VERSION 5.7 ;
BUSBITCHARS "[]" ;
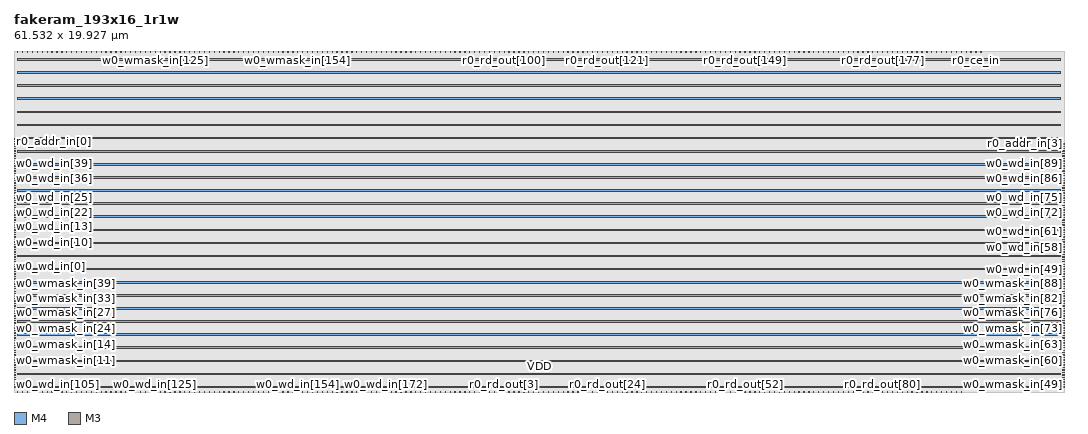
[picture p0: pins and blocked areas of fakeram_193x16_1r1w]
MACRO fakeram_193x16_1r1w
  FOREIGN fakeram_193x16_1r1w 0 0 ;
  SYMMETRY X Y R90 ;
  SIZE 61.532 BY 19.927 ;
  CLASS BLOCK ;
  PIN w0_wmask_in[0]
    DIRECTION INPUT ;
    USE SIGNAL ;
    SHAPE ABUTMENT ;
    PORT
      LAYER M4 ;
      RECT 0.000 0.276 0.072 0.300 ;
    END
  END w0_wmask_in[0]
  PIN w0_wmask_in[1]
    DIRECTION INPUT ;
    USE SIGNAL ;
    SHAPE ABUTMENT ;
    PORT
      LAYER M4 ;
      RECT 0.000 0.420 0.072 0.444 ;
    END
  END w0_wmask_in[1]
  PIN w0_wmask_in[2]
    DIRECTION INPUT ;
    USE SIGNAL ;
    SHAPE ABUTMENT ;
    PORT
      LAYER M4 ;
      RECT 0.000 0.564 0.072 0.588 ;
    END
  END w0_wmask_in[2]
  PIN w0_wmask_in[3]
    DIRECTION INPUT ;
    USE SIGNAL ;
    SHAPE ABUTMENT ;
    PORT
      LAYER M4 ;
      RECT 0.000 0.708 0.072 0.732 ;
    END
  END w0_wmask_in[3]
  PIN w0_wmask_in[4]
    DIRECTION INPUT ;
    USE SIGNAL ;
    SHAPE ABUTMENT ;
    PORT
      LAYER M4 ;
      RECT 0.000 0.852 0.072 0.876 ;
    END
  END w0_wmask_in[4]
  PIN w0_wmask_in[5]
    DIRECTION INPUT ;
    USE SIGNAL ;
    SHAPE ABUTMENT ;
    PORT
      LAYER M4 ;
      RECT 0.000 0.996 0.072 1.020 ;
    END
  END w0_wmask_in[5]
  PIN w0_wmask_in[6]
    DIRECTION INPUT ;
    USE SIGNAL ;
    SHAPE ABUTMENT ;
    PORT
      LAYER M4 ;
      RECT 0.000 1.140 0.072 1.164 ;
    END
  END w0_wmask_in[6]
  PIN w0_wmask_in[7]
    DIRECTION INPUT ;
    USE SIGNAL ;
    SHAPE ABUTMENT ;
    PORT
      LAYER M4 ;
      RECT 0.000 1.284 0.072 1.308 ;
    END
  END w0_wmask_in[7]
  PIN w0_wmask_in[8]
    DIRECTION INPUT ;
    USE SIGNAL ;
    SHAPE ABUTMENT ;
    PORT
      LAYER M4 ;
      RECT 0.000 1.428 0.072 1.452 ;
    END
  END w0_wmask_in[8]
  PIN w0_wmask_in[9]
    DIRECTION INPUT ;
    USE SIGNAL ;
    SHAPE ABUTMENT ;
    PORT
      LAYER M4 ;
      RECT 0.000 1.572 0.072 1.596 ;
    END
  END w0_wmask_in[9]
  PIN w0_wmask_in[10]
    DIRECTION INPUT ;
    USE SIGNAL ;
    SHAPE ABUTMENT ;
    PORT
      LAYER M4 ;
      RECT 0.000 1.716 0.072 1.740 ;
    END
  END w0_wmask_in[10]
  PIN w0_wmask_in[11]
    DIRECTION INPUT ;
    USE SIGNAL ;
    SHAPE ABUTMENT ;
    PORT
      LAYER M4 ;
      RECT 0.000 1.860 0.072 1.884 ;
    END
  END w0_wmask_in[11]
  PIN w0_wmask_in[12]
    DIRECTION INPUT ;
    USE SIGNAL ;
    SHAPE ABUTMENT ;
    PORT
      LAYER M4 ;
      RECT 0.000 2.004 0.072 2.028 ;
    END
  END w0_wmask_in[12]
  PIN w0_wmask_in[13]
    DIRECTION INPUT ;
    USE SIGNAL ;
    SHAPE ABUTMENT ;
    PORT
      LAYER M4 ;
      RECT 0.000 2.148 0.072 2.172 ;
    END
  END w0_wmask_in[13]
  PIN w0_wmask_in[14]
    DIRECTION INPUT ;
    USE SIGNAL ;
    SHAPE ABUTMENT ;
    PORT
      LAYER M4 ;
      RECT 0.000 2.292 0.072 2.316 ;
    END
  END w0_wmask_in[14]
  PIN w0_wmask_in[15]
    DIRECTION INPUT ;
    USE SIGNAL ;
    SHAPE ABUTMENT ;
    PORT
      LAYER M4 ;
      RECT 0.000 2.436 0.072 2.460 ;
    END
  END w0_wmask_in[15]
  PIN w0_wmask_in[16]
    DIRECTION INPUT ;
    USE SIGNAL ;
    SHAPE ABUTMENT ;
    PORT
      LAYER M4 ;
      RECT 0.000 2.580 0.072 2.604 ;
    END
  END w0_wmask_in[16]
  PIN w0_wmask_in[17]
    DIRECTION INPUT ;
    USE SIGNAL ;
    SHAPE ABUTMENT ;
    PORT
      LAYER M4 ;
      RECT 0.000 2.724 0.072 2.748 ;
    END
  END w0_wmask_in[17]
  PIN w0_wmask_in[18]
    DIRECTION INPUT ;
    USE SIGNAL ;
    SHAPE ABUTMENT ;
    PORT
      LAYER M4 ;
      RECT 0.000 2.868 0.072 2.892 ;
    END
  END w0_wmask_in[18]
  PIN w0_wmask_in[19]
    DIRECTION INPUT ;
    USE SIGNAL ;
    SHAPE ABUTMENT ;
    PORT
      LAYER M4 ;
      RECT 0.000 3.012 0.072 3.036 ;
    END
  END w0_wmask_in[19]
  PIN w0_wmask_in[20]
    DIRECTION INPUT ;
    USE SIGNAL ;
    SHAPE ABUTMENT ;
    PORT
      LAYER M4 ;
      RECT 0.000 3.156 0.072 3.180 ;
    END
  END w0_wmask_in[20]
  PIN w0_wmask_in[21]
    DIRECTION INPUT ;
    USE SIGNAL ;
    SHAPE ABUTMENT ;
    PORT
      LAYER M4 ;
      RECT 0.000 3.300 0.072 3.324 ;
    END
  END w0_wmask_in[21]
  PIN w0_wmask_in[22]
    DIRECTION INPUT ;
    USE SIGNAL ;
    SHAPE ABUTMENT ;
    PORT
      LAYER M4 ;
      RECT 0.000 3.444 0.072 3.468 ;
    END
  END w0_wmask_in[22]
  PIN w0_wmask_in[23]
    DIRECTION INPUT ;
    USE SIGNAL ;
    SHAPE ABUTMENT ;
    PORT
      LAYER M4 ;
      RECT 0.000 3.588 0.072 3.612 ;
    END
  END w0_wmask_in[23]
  PIN w0_wmask_in[24]
    DIRECTION INPUT ;
    USE SIGNAL ;
    SHAPE ABUTMENT ;
    PORT
      LAYER M4 ;
      RECT 0.000 3.732 0.072 3.756 ;
    END
  END w0_wmask_in[24]
  PIN w0_wmask_in[25]
    DIRECTION INPUT ;
    USE SIGNAL ;
    SHAPE ABUTMENT ;
    PORT
      LAYER M4 ;
      RECT 0.000 3.876 0.072 3.900 ;
    END
  END w0_wmask_in[25]
  PIN w0_wmask_in[26]
    DIRECTION INPUT ;
    USE SIGNAL ;
    SHAPE ABUTMENT ;
    PORT
      LAYER M4 ;
      RECT 0.000 4.020 0.072 4.044 ;
    END
  END w0_wmask_in[26]
  PIN w0_wmask_in[27]
    DIRECTION INPUT ;
    USE SIGNAL ;
    SHAPE ABUTMENT ;
    PORT
      LAYER M4 ;
      RECT 0.000 4.164 0.072 4.188 ;
    END
  END w0_wmask_in[27]
  PIN w0_wmask_in[28]
    DIRECTION INPUT ;
    USE SIGNAL ;
    SHAPE ABUTMENT ;
    PORT
      LAYER M4 ;
      RECT 0.000 4.308 0.072 4.332 ;
    END
  END w0_wmask_in[28]
  PIN w0_wmask_in[29]
    DIRECTION INPUT ;
    USE SIGNAL ;
    SHAPE ABUTMENT ;
    PORT
      LAYER M4 ;
      RECT 0.000 4.452 0.072 4.476 ;
    END
  END w0_wmask_in[29]
  PIN w0_wmask_in[30]
    DIRECTION INPUT ;
    USE SIGNAL ;
    SHAPE ABUTMENT ;
    PORT
      LAYER M4 ;
      RECT 0.000 4.596 0.072 4.620 ;
    END
  END w0_wmask_in[30]
  PIN w0_wmask_in[31]
    DIRECTION INPUT ;
    USE SIGNAL ;
    SHAPE ABUTMENT ;
    PORT
      LAYER M4 ;
      RECT 0.000 4.740 0.072 4.764 ;
    END
  END w0_wmask_in[31]
  PIN w0_wmask_in[32]
    DIRECTION INPUT ;
    USE SIGNAL ;
    SHAPE ABUTMENT ;
    PORT
      LAYER M4 ;
      RECT 0.000 4.884 0.072 4.908 ;
    END
  END w0_wmask_in[32]
  PIN w0_wmask_in[33]
    DIRECTION INPUT ;
    USE SIGNAL ;
    SHAPE ABUTMENT ;
    PORT
      LAYER M4 ;
      RECT 0.000 5.028 0.072 5.052 ;
    END
  END w0_wmask_in[33]
  PIN w0_wmask_in[34]
    DIRECTION INPUT ;
    USE SIGNAL ;
    SHAPE ABUTMENT ;
    PORT
      LAYER M4 ;
      RECT 0.000 5.172 0.072 5.196 ;
    END
  END w0_wmask_in[34]
  PIN w0_wmask_in[35]
    DIRECTION INPUT ;
    USE SIGNAL ;
    SHAPE ABUTMENT ;
    PORT
      LAYER M4 ;
      RECT 0.000 5.316 0.072 5.340 ;
    END
  END w0_wmask_in[35]
  PIN w0_wmask_in[36]
    DIRECTION INPUT ;
    USE SIGNAL ;
    SHAPE ABUTMENT ;
    PORT
      LAYER M4 ;
      RECT 0.000 5.460 0.072 5.484 ;
    END
  END w0_wmask_in[36]
  PIN w0_wmask_in[37]
    DIRECTION INPUT ;
    USE SIGNAL ;
    SHAPE ABUTMENT ;
    PORT
      LAYER M4 ;
      RECT 0.000 5.604 0.072 5.628 ;
    END
  END w0_wmask_in[37]
  PIN w0_wmask_in[38]
    DIRECTION INPUT ;
    USE SIGNAL ;
    SHAPE ABUTMENT ;
    PORT
      LAYER M4 ;
      RECT 0.000 5.748 0.072 5.772 ;
    END
  END w0_wmask_in[38]
  PIN w0_wmask_in[39]
    DIRECTION INPUT ;
    USE SIGNAL ;
    SHAPE ABUTMENT ;
    PORT
      LAYER M4 ;
      RECT 0.000 5.892 0.072 5.916 ;
    END
  END w0_wmask_in[39]
  PIN w0_wmask_in[40]
    DIRECTION INPUT ;
    USE SIGNAL ;
    SHAPE ABUTMENT ;
    PORT
      LAYER M4 ;
      RECT 0.000 6.036 0.072 6.060 ;
    END
  END w0_wmask_in[40]
  PIN w0_wmask_in[41]
    DIRECTION INPUT ;
    USE SIGNAL ;
    SHAPE ABUTMENT ;
    PORT
      LAYER M4 ;
      RECT 0.000 6.180 0.072 6.204 ;
    END
  END w0_wmask_in[41]
  PIN w0_wmask_in[42]
    DIRECTION INPUT ;
    USE SIGNAL ;
    SHAPE ABUTMENT ;
    PORT
      LAYER M4 ;
      RECT 0.000 6.324 0.072 6.348 ;
    END
  END w0_wmask_in[42]
  PIN w0_wmask_in[43]
    DIRECTION INPUT ;
    USE SIGNAL ;
    SHAPE ABUTMENT ;
    PORT
      LAYER M4 ;
      RECT 0.000 6.468 0.072 6.492 ;
    END
  END w0_wmask_in[43]
  PIN w0_wmask_in[44]
    DIRECTION INPUT ;
    USE SIGNAL ;
    SHAPE ABUTMENT ;
    PORT
      LAYER M4 ;
      RECT 0.000 6.612 0.072 6.636 ;
    END
  END w0_wmask_in[44]
  PIN w0_wmask_in[45]
    DIRECTION INPUT ;
    USE SIGNAL ;
    SHAPE ABUTMENT ;
    PORT
      LAYER M4 ;
      RECT 0.000 6.756 0.072 6.780 ;
    END
  END w0_wmask_in[45]
  PIN w0_wmask_in[46]
    DIRECTION INPUT ;
    USE SIGNAL ;
    SHAPE ABUTMENT ;
    PORT
      LAYER M4 ;
      RECT 0.000 6.900 0.072 6.924 ;
    END
  END w0_wmask_in[46]
  PIN w0_wmask_in[47]
    DIRECTION INPUT ;
    USE SIGNAL ;
    SHAPE ABUTMENT ;
    PORT
      LAYER M4 ;
      RECT 0.000 7.044 0.072 7.068 ;
    END
  END w0_wmask_in[47]
  PIN w0_wmask_in[48]
    DIRECTION INPUT ;
    USE SIGNAL ;
    SHAPE ABUTMENT ;
    PORT
      LAYER M4 ;
      RECT 0.000 7.188 0.072 7.212 ;
    END
  END w0_wmask_in[48]
  PIN w0_wmask_in[49]
    DIRECTION INPUT ;
    USE SIGNAL ;
    SHAPE ABUTMENT ;
    PORT
      LAYER M4 ;
      RECT 61.460 0.276 61.532 0.300 ;
    END
  END w0_wmask_in[49]
  PIN w0_wmask_in[50]
    DIRECTION INPUT ;
    USE SIGNAL ;
    SHAPE ABUTMENT ;
    PORT
      LAYER M4 ;
      RECT 61.460 0.420 61.532 0.444 ;
    END
  END w0_wmask_in[50]
  PIN w0_wmask_in[51]
    DIRECTION INPUT ;
    USE SIGNAL ;
    SHAPE ABUTMENT ;
    PORT
      LAYER M4 ;
      RECT 61.460 0.564 61.532 0.588 ;
    END
  END w0_wmask_in[51]
  PIN w0_wmask_in[52]
    DIRECTION INPUT ;
    USE SIGNAL ;
    SHAPE ABUTMENT ;
    PORT
      LAYER M4 ;
      RECT 61.460 0.708 61.532 0.732 ;
    END
  END w0_wmask_in[52]
  PIN w0_wmask_in[53]
    DIRECTION INPUT ;
    USE SIGNAL ;
    SHAPE ABUTMENT ;
    PORT
      LAYER M4 ;
      RECT 61.460 0.852 61.532 0.876 ;
    END
  END w0_wmask_in[53]
  PIN w0_wmask_in[54]
    DIRECTION INPUT ;
    USE SIGNAL ;
    SHAPE ABUTMENT ;
    PORT
      LAYER M4 ;
      RECT 61.460 0.996 61.532 1.020 ;
    END
  END w0_wmask_in[54]
  PIN w0_wmask_in[55]
    DIRECTION INPUT ;
    USE SIGNAL ;
    SHAPE ABUTMENT ;
    PORT
      LAYER M4 ;
      RECT 61.460 1.140 61.532 1.164 ;
    END
  END w0_wmask_in[55]
  PIN w0_wmask_in[56]
    DIRECTION INPUT ;
    USE SIGNAL ;
    SHAPE ABUTMENT ;
    PORT
      LAYER M4 ;
      RECT 61.460 1.284 61.532 1.308 ;
    END
  END w0_wmask_in[56]
  PIN w0_wmask_in[57]
    DIRECTION INPUT ;
    USE SIGNAL ;
    SHAPE ABUTMENT ;
    PORT
      LAYER M4 ;
      RECT 61.460 1.428 61.532 1.452 ;
    END
  END w0_wmask_in[57]
  PIN w0_wmask_in[58]
    DIRECTION INPUT ;
    USE SIGNAL ;
    SHAPE ABUTMENT ;
    PORT
      LAYER M4 ;
      RECT 61.460 1.572 61.532 1.596 ;
    END
  END w0_wmask_in[58]
  PIN w0_wmask_in[59]
    DIRECTION INPUT ;
    USE SIGNAL ;
    SHAPE ABUTMENT ;
    PORT
      LAYER M4 ;
      RECT 61.460 1.716 61.532 1.740 ;
    END
  END w0_wmask_in[59]
  PIN w0_wmask_in[60]
    DIRECTION INPUT ;
    USE SIGNAL ;
    SHAPE ABUTMENT ;
    PORT
      LAYER M4 ;
      RECT 61.460 1.860 61.532 1.884 ;
    END
  END w0_wmask_in[60]
  PIN w0_wmask_in[61]
    DIRECTION INPUT ;
    USE SIGNAL ;
    SHAPE ABUTMENT ;
    PORT
      LAYER M4 ;
      RECT 61.460 2.004 61.532 2.028 ;
    END
  END w0_wmask_in[61]
  PIN w0_wmask_in[62]
    DIRECTION INPUT ;
    USE SIGNAL ;
    SHAPE ABUTMENT ;
    PORT
      LAYER M4 ;
      RECT 61.460 2.148 61.532 2.172 ;
    END
  END w0_wmask_in[62]
  PIN w0_wmask_in[63]
    DIRECTION INPUT ;
    USE SIGNAL ;
    SHAPE ABUTMENT ;
    PORT
      LAYER M4 ;
      RECT 61.460 2.292 61.532 2.316 ;
    END
  END w0_wmask_in[63]
  PIN w0_wmask_in[64]
    DIRECTION INPUT ;
    USE SIGNAL ;
    SHAPE ABUTMENT ;
    PORT
      LAYER M4 ;
      RECT 61.460 2.436 61.532 2.460 ;
    END
  END w0_wmask_in[64]
  PIN w0_wmask_in[65]
    DIRECTION INPUT ;
    USE SIGNAL ;
    SHAPE ABUTMENT ;
    PORT
      LAYER M4 ;
      RECT 61.460 2.580 61.532 2.604 ;
    END
  END w0_wmask_in[65]
  PIN w0_wmask_in[66]
    DIRECTION INPUT ;
    USE SIGNAL ;
    SHAPE ABUTMENT ;
    PORT
      LAYER M4 ;
      RECT 61.460 2.724 61.532 2.748 ;
    END
  END w0_wmask_in[66]
  PIN w0_wmask_in[67]
    DIRECTION INPUT ;
    USE SIGNAL ;
    SHAPE ABUTMENT ;
    PORT
      LAYER M4 ;
      RECT 61.460 2.868 61.532 2.892 ;
    END
  END w0_wmask_in[67]
  PIN w0_wmask_in[68]
    DIRECTION INPUT ;
    USE SIGNAL ;
    SHAPE ABUTMENT ;
    PORT
      LAYER M4 ;
      RECT 61.460 3.012 61.532 3.036 ;
    END
  END w0_wmask_in[68]
  PIN w0_wmask_in[69]
    DIRECTION INPUT ;
    USE SIGNAL ;
    SHAPE ABUTMENT ;
    PORT
      LAYER M4 ;
      RECT 61.460 3.156 61.532 3.180 ;
    END
  END w0_wmask_in[69]
  PIN w0_wmask_in[70]
    DIRECTION INPUT ;
    USE SIGNAL ;
    SHAPE ABUTMENT ;
    PORT
      LAYER M4 ;
      RECT 61.460 3.300 61.532 3.324 ;
    END
  END w0_wmask_in[70]
  PIN w0_wmask_in[71]
    DIRECTION INPUT ;
    USE SIGNAL ;
    SHAPE ABUTMENT ;
    PORT
      LAYER M4 ;
      RECT 61.460 3.444 61.532 3.468 ;
    END
  END w0_wmask_in[71]
  PIN w0_wmask_in[72]
    DIRECTION INPUT ;
    USE SIGNAL ;
    SHAPE ABUTMENT ;
    PORT
      LAYER M4 ;
      RECT 61.460 3.588 61.532 3.612 ;
    END
  END w0_wmask_in[72]
  PIN w0_wmask_in[73]
    DIRECTION INPUT ;
    USE SIGNAL ;
    SHAPE ABUTMENT ;
    PORT
      LAYER M4 ;
      RECT 61.460 3.732 61.532 3.756 ;
    END
  END w0_wmask_in[73]
  PIN w0_wmask_in[74]
    DIRECTION INPUT ;
    USE SIGNAL ;
    SHAPE ABUTMENT ;
    PORT
      LAYER M4 ;
      RECT 61.460 3.876 61.532 3.900 ;
    END
  END w0_wmask_in[74]
  PIN w0_wmask_in[75]
    DIRECTION INPUT ;
    USE SIGNAL ;
    SHAPE ABUTMENT ;
    PORT
      LAYER M4 ;
      RECT 61.460 4.020 61.532 4.044 ;
    END
  END w0_wmask_in[75]
  PIN w0_wmask_in[76]
    DIRECTION INPUT ;
    USE SIGNAL ;
    SHAPE ABUTMENT ;
    PORT
      LAYER M4 ;
      RECT 61.460 4.164 61.532 4.188 ;
    END
  END w0_wmask_in[76]
  PIN w0_wmask_in[77]
    DIRECTION INPUT ;
    USE SIGNAL ;
    SHAPE ABUTMENT ;
    PORT
      LAYER M4 ;
      RECT 61.460 4.308 61.532 4.332 ;
    END
  END w0_wmask_in[77]
  PIN w0_wmask_in[78]
    DIRECTION INPUT ;
    USE SIGNAL ;
    SHAPE ABUTMENT ;
    PORT
      LAYER M4 ;
      RECT 61.460 4.452 61.532 4.476 ;
    END
  END w0_wmask_in[78]
  PIN w0_wmask_in[79]
    DIRECTION INPUT ;
    USE SIGNAL ;
    SHAPE ABUTMENT ;
    PORT
      LAYER M4 ;
      RECT 61.460 4.596 61.532 4.620 ;
    END
  END w0_wmask_in[79]
  PIN w0_wmask_in[80]
    DIRECTION INPUT ;
    USE SIGNAL ;
    SHAPE ABUTMENT ;
    PORT
      LAYER M4 ;
      RECT 61.460 4.740 61.532 4.764 ;
    END
  END w0_wmask_in[80]
  PIN w0_wmask_in[81]
    DIRECTION INPUT ;
    USE SIGNAL ;
    SHAPE ABUTMENT ;
    PORT
      LAYER M4 ;
      RECT 61.460 4.884 61.532 4.908 ;
    END
  END w0_wmask_in[81]
  PIN w0_wmask_in[82]
    DIRECTION INPUT ;
    USE SIGNAL ;
    SHAPE ABUTMENT ;
    PORT
      LAYER M4 ;
      RECT 61.460 5.028 61.532 5.052 ;
    END
  END w0_wmask_in[82]
  PIN w0_wmask_in[83]
    DIRECTION INPUT ;
    USE SIGNAL ;
    SHAPE ABUTMENT ;
    PORT
      LAYER M4 ;
      RECT 61.460 5.172 61.532 5.196 ;
    END
  END w0_wmask_in[83]
  PIN w0_wmask_in[84]
    DIRECTION INPUT ;
    USE SIGNAL ;
    SHAPE ABUTMENT ;
    PORT
      LAYER M4 ;
      RECT 61.460 5.316 61.532 5.340 ;
    END
  END w0_wmask_in[84]
  PIN w0_wmask_in[85]
    DIRECTION INPUT ;
    USE SIGNAL ;
    SHAPE ABUTMENT ;
    PORT
      LAYER M4 ;
      RECT 61.460 5.460 61.532 5.484 ;
    END
  END w0_wmask_in[85]
  PIN w0_wmask_in[86]
    DIRECTION INPUT ;
    USE SIGNAL ;
    SHAPE ABUTMENT ;
    PORT
      LAYER M4 ;
      RECT 61.460 5.604 61.532 5.628 ;
    END
  END w0_wmask_in[86]
  PIN w0_wmask_in[87]
    DIRECTION INPUT ;
    USE SIGNAL ;
    SHAPE ABUTMENT ;
    PORT
      LAYER M4 ;
      RECT 61.460 5.748 61.532 5.772 ;
    END
  END w0_wmask_in[87]
  PIN w0_wmask_in[88]
    DIRECTION INPUT ;
    USE SIGNAL ;
    SHAPE ABUTMENT ;
    PORT
      LAYER M4 ;
      RECT 61.460 5.892 61.532 5.916 ;
    END
  END w0_wmask_in[88]
  PIN w0_wmask_in[89]
    DIRECTION INPUT ;
    USE SIGNAL ;
    SHAPE ABUTMENT ;
    PORT
      LAYER M4 ;
      RECT 61.460 6.036 61.532 6.060 ;
    END
  END w0_wmask_in[89]
  PIN w0_wmask_in[90]
    DIRECTION INPUT ;
    USE SIGNAL ;
    SHAPE ABUTMENT ;
    PORT
      LAYER M4 ;
      RECT 61.460 6.180 61.532 6.204 ;
    END
  END w0_wmask_in[90]
  PIN w0_wmask_in[91]
    DIRECTION INPUT ;
    USE SIGNAL ;
    SHAPE ABUTMENT ;
    PORT
      LAYER M4 ;
      RECT 61.460 6.324 61.532 6.348 ;
    END
  END w0_wmask_in[91]
  PIN w0_wmask_in[92]
    DIRECTION INPUT ;
    USE SIGNAL ;
    SHAPE ABUTMENT ;
    PORT
      LAYER M4 ;
      RECT 61.460 6.468 61.532 6.492 ;
    END
  END w0_wmask_in[92]
  PIN w0_wmask_in[93]
    DIRECTION INPUT ;
    USE SIGNAL ;
    SHAPE ABUTMENT ;
    PORT
      LAYER M4 ;
      RECT 61.460 6.612 61.532 6.636 ;
    END
  END w0_wmask_in[93]
  PIN w0_wmask_in[94]
    DIRECTION INPUT ;
    USE SIGNAL ;
    SHAPE ABUTMENT ;
    PORT
      LAYER M4 ;
      RECT 61.460 6.756 61.532 6.780 ;
    END
  END w0_wmask_in[94]
  PIN w0_wmask_in[95]
    DIRECTION INPUT ;
    USE SIGNAL ;
    SHAPE ABUTMENT ;
    PORT
      LAYER M4 ;
      RECT 61.460 6.900 61.532 6.924 ;
    END
  END w0_wmask_in[95]
  PIN w0_wmask_in[96]
    DIRECTION INPUT ;
    USE SIGNAL ;
    SHAPE ABUTMENT ;
    PORT
      LAYER M4 ;
      RECT 61.460 7.044 61.532 7.068 ;
    END
  END w0_wmask_in[96]
  PIN w0_wmask_in[97]
    DIRECTION INPUT ;
    USE SIGNAL ;
    SHAPE ABUTMENT ;
    PORT
      LAYER M3 ;
      RECT 0.207 19.873 0.225 19.927 ;
    END
  END w0_wmask_in[97]
  PIN w0_wmask_in[98]
    DIRECTION INPUT ;
    USE SIGNAL ;
    SHAPE ABUTMENT ;
    PORT
      LAYER M3 ;
      RECT 0.495 19.873 0.513 19.927 ;
    END
  END w0_wmask_in[98]
  PIN w0_wmask_in[99]
    DIRECTION INPUT ;
    USE SIGNAL ;
    SHAPE ABUTMENT ;
    PORT
      LAYER M3 ;
      RECT 0.783 19.873 0.801 19.927 ;
    END
  END w0_wmask_in[99]
  PIN w0_wmask_in[100]
    DIRECTION INPUT ;
    USE SIGNAL ;
    SHAPE ABUTMENT ;
    PORT
      LAYER M3 ;
      RECT 1.071 19.873 1.089 19.927 ;
    END
  END w0_wmask_in[100]
  PIN w0_wmask_in[101]
    DIRECTION INPUT ;
    USE SIGNAL ;
    SHAPE ABUTMENT ;
    PORT
      LAYER M3 ;
      RECT 1.359 19.873 1.377 19.927 ;
    END
  END w0_wmask_in[101]
  PIN w0_wmask_in[102]
    DIRECTION INPUT ;
    USE SIGNAL ;
    SHAPE ABUTMENT ;
    PORT
      LAYER M3 ;
      RECT 1.647 19.873 1.665 19.927 ;
    END
  END w0_wmask_in[102]
  PIN w0_wmask_in[103]
    DIRECTION INPUT ;
    USE SIGNAL ;
    SHAPE ABUTMENT ;
    PORT
      LAYER M3 ;
      RECT 1.935 19.873 1.953 19.927 ;
    END
  END w0_wmask_in[103]
  PIN w0_wmask_in[104]
    DIRECTION INPUT ;
    USE SIGNAL ;
    SHAPE ABUTMENT ;
    PORT
      LAYER M3 ;
      RECT 2.223 19.873 2.241 19.927 ;
    END
  END w0_wmask_in[104]
  PIN w0_wmask_in[105]
    DIRECTION INPUT ;
    USE SIGNAL ;
    SHAPE ABUTMENT ;
    PORT
      LAYER M3 ;
      RECT 2.511 19.873 2.529 19.927 ;
    END
  END w0_wmask_in[105]
  PIN w0_wmask_in[106]
    DIRECTION INPUT ;
    USE SIGNAL ;
    SHAPE ABUTMENT ;
    PORT
      LAYER M3 ;
      RECT 2.799 19.873 2.817 19.927 ;
    END
  END w0_wmask_in[106]
  PIN w0_wmask_in[107]
    DIRECTION INPUT ;
    USE SIGNAL ;
    SHAPE ABUTMENT ;
    PORT
      LAYER M3 ;
      RECT 3.087 19.873 3.105 19.927 ;
    END
  END w0_wmask_in[107]
  PIN w0_wmask_in[108]
    DIRECTION INPUT ;
    USE SIGNAL ;
    SHAPE ABUTMENT ;
    PORT
      LAYER M3 ;
      RECT 3.375 19.873 3.393 19.927 ;
    END
  END w0_wmask_in[108]
  PIN w0_wmask_in[109]
    DIRECTION INPUT ;
    USE SIGNAL ;
    SHAPE ABUTMENT ;
    PORT
      LAYER M3 ;
      RECT 3.663 19.873 3.681 19.927 ;
    END
  END w0_wmask_in[109]
  PIN w0_wmask_in[110]
    DIRECTION INPUT ;
    USE SIGNAL ;
    SHAPE ABUTMENT ;
    PORT
      LAYER M3 ;
      RECT 3.951 19.873 3.969 19.927 ;
    END
  END w0_wmask_in[110]
  PIN w0_wmask_in[111]
    DIRECTION INPUT ;
    USE SIGNAL ;
    SHAPE ABUTMENT ;
    PORT
      LAYER M3 ;
      RECT 4.239 19.873 4.257 19.927 ;
    END
  END w0_wmask_in[111]
  PIN w0_wmask_in[112]
    DIRECTION INPUT ;
    USE SIGNAL ;
    SHAPE ABUTMENT ;
    PORT
      LAYER M3 ;
      RECT 4.527 19.873 4.545 19.927 ;
    END
  END w0_wmask_in[112]
  PIN w0_wmask_in[113]
    DIRECTION INPUT ;
    USE SIGNAL ;
    SHAPE ABUTMENT ;
    PORT
      LAYER M3 ;
      RECT 4.815 19.873 4.833 19.927 ;
    END
  END w0_wmask_in[113]
  PIN w0_wmask_in[114]
    DIRECTION INPUT ;
    USE SIGNAL ;
    SHAPE ABUTMENT ;
    PORT
      LAYER M3 ;
      RECT 5.103 19.873 5.121 19.927 ;
    END
  END w0_wmask_in[114]
  PIN w0_wmask_in[115]
    DIRECTION INPUT ;
    USE SIGNAL ;
    SHAPE ABUTMENT ;
    PORT
      LAYER M3 ;
      RECT 5.391 19.873 5.409 19.927 ;
    END
  END w0_wmask_in[115]
  PIN w0_wmask_in[116]
    DIRECTION INPUT ;
    USE SIGNAL ;
    SHAPE ABUTMENT ;
    PORT
      LAYER M3 ;
      RECT 5.679 19.873 5.697 19.927 ;
    END
  END w0_wmask_in[116]
  PIN w0_wmask_in[117]
    DIRECTION INPUT ;
    USE SIGNAL ;
    SHAPE ABUTMENT ;
    PORT
      LAYER M3 ;
      RECT 5.967 19.873 5.985 19.927 ;
    END
  END w0_wmask_in[117]
  PIN w0_wmask_in[118]
    DIRECTION INPUT ;
    USE SIGNAL ;
    SHAPE ABUTMENT ;
    PORT
      LAYER M3 ;
      RECT 6.255 19.873 6.273 19.927 ;
    END
  END w0_wmask_in[118]
  PIN w0_wmask_in[119]
    DIRECTION INPUT ;
    USE SIGNAL ;
    SHAPE ABUTMENT ;
    PORT
      LAYER M3 ;
      RECT 6.543 19.873 6.561 19.927 ;
    END
  END w0_wmask_in[119]
  PIN w0_wmask_in[120]
    DIRECTION INPUT ;
    USE SIGNAL ;
    SHAPE ABUTMENT ;
    PORT
      LAYER M3 ;
      RECT 6.831 19.873 6.849 19.927 ;
    END
  END w0_wmask_in[120]
  PIN w0_wmask_in[121]
    DIRECTION INPUT ;
    USE SIGNAL ;
    SHAPE ABUTMENT ;
    PORT
      LAYER M3 ;
      RECT 7.119 19.873 7.137 19.927 ;
    END
  END w0_wmask_in[121]
  PIN w0_wmask_in[122]
    DIRECTION INPUT ;
    USE SIGNAL ;
    SHAPE ABUTMENT ;
    PORT
      LAYER M3 ;
      RECT 7.407 19.873 7.425 19.927 ;
    END
  END w0_wmask_in[122]
  PIN w0_wmask_in[123]
    DIRECTION INPUT ;
    USE SIGNAL ;
    SHAPE ABUTMENT ;
    PORT
      LAYER M3 ;
      RECT 7.695 19.873 7.713 19.927 ;
    END
  END w0_wmask_in[123]
  PIN w0_wmask_in[124]
    DIRECTION INPUT ;
    USE SIGNAL ;
    SHAPE ABUTMENT ;
    PORT
      LAYER M3 ;
      RECT 7.983 19.873 8.001 19.927 ;
    END
  END w0_wmask_in[124]
  PIN w0_wmask_in[125]
    DIRECTION INPUT ;
    USE SIGNAL ;
    SHAPE ABUTMENT ;
    PORT
      LAYER M3 ;
      RECT 8.271 19.873 8.289 19.927 ;
    END
  END w0_wmask_in[125]
  PIN w0_wmask_in[126]
    DIRECTION INPUT ;
    USE SIGNAL ;
    SHAPE ABUTMENT ;
    PORT
      LAYER M3 ;
      RECT 8.559 19.873 8.577 19.927 ;
    END
  END w0_wmask_in[126]
  PIN w0_wmask_in[127]
    DIRECTION INPUT ;
    USE SIGNAL ;
    SHAPE ABUTMENT ;
    PORT
      LAYER M3 ;
      RECT 8.847 19.873 8.865 19.927 ;
    END
  END w0_wmask_in[127]
  PIN w0_wmask_in[128]
    DIRECTION INPUT ;
    USE SIGNAL ;
    SHAPE ABUTMENT ;
    PORT
      LAYER M3 ;
      RECT 9.135 19.873 9.153 19.927 ;
    END
  END w0_wmask_in[128]
  PIN w0_wmask_in[129]
    DIRECTION INPUT ;
    USE SIGNAL ;
    SHAPE ABUTMENT ;
    PORT
      LAYER M3 ;
      RECT 9.423 19.873 9.441 19.927 ;
    END
  END w0_wmask_in[129]
  PIN w0_wmask_in[130]
    DIRECTION INPUT ;
    USE SIGNAL ;
    SHAPE ABUTMENT ;
    PORT
      LAYER M3 ;
      RECT 9.711 19.873 9.729 19.927 ;
    END
  END w0_wmask_in[130]
  PIN w0_wmask_in[131]
    DIRECTION INPUT ;
    USE SIGNAL ;
    SHAPE ABUTMENT ;
    PORT
      LAYER M3 ;
      RECT 9.999 19.873 10.017 19.927 ;
    END
  END w0_wmask_in[131]
  PIN w0_wmask_in[132]
    DIRECTION INPUT ;
    USE SIGNAL ;
    SHAPE ABUTMENT ;
    PORT
      LAYER M3 ;
      RECT 10.287 19.873 10.305 19.927 ;
    END
  END w0_wmask_in[132]
  PIN w0_wmask_in[133]
    DIRECTION INPUT ;
    USE SIGNAL ;
    SHAPE ABUTMENT ;
    PORT
      LAYER M3 ;
      RECT 10.575 19.873 10.593 19.927 ;
    END
  END w0_wmask_in[133]
  PIN w0_wmask_in[134]
    DIRECTION INPUT ;
    USE SIGNAL ;
    SHAPE ABUTMENT ;
    PORT
      LAYER M3 ;
      RECT 10.863 19.873 10.881 19.927 ;
    END
  END w0_wmask_in[134]
  PIN w0_wmask_in[135]
    DIRECTION INPUT ;
    USE SIGNAL ;
    SHAPE ABUTMENT ;
    PORT
      LAYER M3 ;
      RECT 11.151 19.873 11.169 19.927 ;
    END
  END w0_wmask_in[135]
  PIN w0_wmask_in[136]
    DIRECTION INPUT ;
    USE SIGNAL ;
    SHAPE ABUTMENT ;
    PORT
      LAYER M3 ;
      RECT 11.439 19.873 11.457 19.927 ;
    END
  END w0_wmask_in[136]
  PIN w0_wmask_in[137]
    DIRECTION INPUT ;
    USE SIGNAL ;
    SHAPE ABUTMENT ;
    PORT
      LAYER M3 ;
      RECT 11.727 19.873 11.745 19.927 ;
    END
  END w0_wmask_in[137]
  PIN w0_wmask_in[138]
    DIRECTION INPUT ;
    USE SIGNAL ;
    SHAPE ABUTMENT ;
    PORT
      LAYER M3 ;
      RECT 12.015 19.873 12.033 19.927 ;
    END
  END w0_wmask_in[138]
  PIN w0_wmask_in[139]
    DIRECTION INPUT ;
    USE SIGNAL ;
    SHAPE ABUTMENT ;
    PORT
      LAYER M3 ;
      RECT 12.303 19.873 12.321 19.927 ;
    END
  END w0_wmask_in[139]
  PIN w0_wmask_in[140]
    DIRECTION INPUT ;
    USE SIGNAL ;
    SHAPE ABUTMENT ;
    PORT
      LAYER M3 ;
      RECT 12.591 19.873 12.609 19.927 ;
    END
  END w0_wmask_in[140]
  PIN w0_wmask_in[141]
    DIRECTION INPUT ;
    USE SIGNAL ;
    SHAPE ABUTMENT ;
    PORT
      LAYER M3 ;
      RECT 12.879 19.873 12.897 19.927 ;
    END
  END w0_wmask_in[141]
  PIN w0_wmask_in[142]
    DIRECTION INPUT ;
    USE SIGNAL ;
    SHAPE ABUTMENT ;
    PORT
      LAYER M3 ;
      RECT 13.167 19.873 13.185 19.927 ;
    END
  END w0_wmask_in[142]
  PIN w0_wmask_in[143]
    DIRECTION INPUT ;
    USE SIGNAL ;
    SHAPE ABUTMENT ;
    PORT
      LAYER M3 ;
      RECT 13.455 19.873 13.473 19.927 ;
    END
  END w0_wmask_in[143]
  PIN w0_wmask_in[144]
    DIRECTION INPUT ;
    USE SIGNAL ;
    SHAPE ABUTMENT ;
    PORT
      LAYER M3 ;
      RECT 13.743 19.873 13.761 19.927 ;
    END
  END w0_wmask_in[144]
  PIN w0_wmask_in[145]
    DIRECTION INPUT ;
    USE SIGNAL ;
    SHAPE ABUTMENT ;
    PORT
      LAYER M3 ;
      RECT 14.031 19.873 14.049 19.927 ;
    END
  END w0_wmask_in[145]
  PIN w0_wmask_in[146]
    DIRECTION INPUT ;
    USE SIGNAL ;
    SHAPE ABUTMENT ;
    PORT
      LAYER M3 ;
      RECT 14.319 19.873 14.337 19.927 ;
    END
  END w0_wmask_in[146]
  PIN w0_wmask_in[147]
    DIRECTION INPUT ;
    USE SIGNAL ;
    SHAPE ABUTMENT ;
    PORT
      LAYER M3 ;
      RECT 14.607 19.873 14.625 19.927 ;
    END
  END w0_wmask_in[147]
  PIN w0_wmask_in[148]
    DIRECTION INPUT ;
    USE SIGNAL ;
    SHAPE ABUTMENT ;
    PORT
      LAYER M3 ;
      RECT 14.895 19.873 14.913 19.927 ;
    END
  END w0_wmask_in[148]
  PIN w0_wmask_in[149]
    DIRECTION INPUT ;
    USE SIGNAL ;
    SHAPE ABUTMENT ;
    PORT
      LAYER M3 ;
      RECT 15.183 19.873 15.201 19.927 ;
    END
  END w0_wmask_in[149]
  PIN w0_wmask_in[150]
    DIRECTION INPUT ;
    USE SIGNAL ;
    SHAPE ABUTMENT ;
    PORT
      LAYER M3 ;
      RECT 15.471 19.873 15.489 19.927 ;
    END
  END w0_wmask_in[150]
  PIN w0_wmask_in[151]
    DIRECTION INPUT ;
    USE SIGNAL ;
    SHAPE ABUTMENT ;
    PORT
      LAYER M3 ;
      RECT 15.759 19.873 15.777 19.927 ;
    END
  END w0_wmask_in[151]
  PIN w0_wmask_in[152]
    DIRECTION INPUT ;
    USE SIGNAL ;
    SHAPE ABUTMENT ;
    PORT
      LAYER M3 ;
      RECT 16.047 19.873 16.065 19.927 ;
    END
  END w0_wmask_in[152]
  PIN w0_wmask_in[153]
    DIRECTION INPUT ;
    USE SIGNAL ;
    SHAPE ABUTMENT ;
    PORT
      LAYER M3 ;
      RECT 16.335 19.873 16.353 19.927 ;
    END
  END w0_wmask_in[153]
  PIN w0_wmask_in[154]
    DIRECTION INPUT ;
    USE SIGNAL ;
    SHAPE ABUTMENT ;
    PORT
      LAYER M3 ;
      RECT 16.623 19.873 16.641 19.927 ;
    END
  END w0_wmask_in[154]
  PIN w0_wmask_in[155]
    DIRECTION INPUT ;
    USE SIGNAL ;
    SHAPE ABUTMENT ;
    PORT
      LAYER M3 ;
      RECT 16.911 19.873 16.929 19.927 ;
    END
  END w0_wmask_in[155]
  PIN w0_wmask_in[156]
    DIRECTION INPUT ;
    USE SIGNAL ;
    SHAPE ABUTMENT ;
    PORT
      LAYER M3 ;
      RECT 17.199 19.873 17.217 19.927 ;
    END
  END w0_wmask_in[156]
  PIN w0_wmask_in[157]
    DIRECTION INPUT ;
    USE SIGNAL ;
    SHAPE ABUTMENT ;
    PORT
      LAYER M3 ;
      RECT 17.487 19.873 17.505 19.927 ;
    END
  END w0_wmask_in[157]
  PIN w0_wmask_in[158]
    DIRECTION INPUT ;
    USE SIGNAL ;
    SHAPE ABUTMENT ;
    PORT
      LAYER M3 ;
      RECT 17.775 19.873 17.793 19.927 ;
    END
  END w0_wmask_in[158]
  PIN w0_wmask_in[159]
    DIRECTION INPUT ;
    USE SIGNAL ;
    SHAPE ABUTMENT ;
    PORT
      LAYER M3 ;
      RECT 18.063 19.873 18.081 19.927 ;
    END
  END w0_wmask_in[159]
  PIN w0_wmask_in[160]
    DIRECTION INPUT ;
    USE SIGNAL ;
    SHAPE ABUTMENT ;
    PORT
      LAYER M3 ;
      RECT 18.351 19.873 18.369 19.927 ;
    END
  END w0_wmask_in[160]
  PIN w0_wmask_in[161]
    DIRECTION INPUT ;
    USE SIGNAL ;
    SHAPE ABUTMENT ;
    PORT
      LAYER M3 ;
      RECT 18.639 19.873 18.657 19.927 ;
    END
  END w0_wmask_in[161]
  PIN w0_wmask_in[162]
    DIRECTION INPUT ;
    USE SIGNAL ;
    SHAPE ABUTMENT ;
    PORT
      LAYER M3 ;
      RECT 18.927 19.873 18.945 19.927 ;
    END
  END w0_wmask_in[162]
  PIN w0_wmask_in[163]
    DIRECTION INPUT ;
    USE SIGNAL ;
    SHAPE ABUTMENT ;
    PORT
      LAYER M3 ;
      RECT 19.215 19.873 19.233 19.927 ;
    END
  END w0_wmask_in[163]
  PIN w0_wmask_in[164]
    DIRECTION INPUT ;
    USE SIGNAL ;
    SHAPE ABUTMENT ;
    PORT
      LAYER M3 ;
      RECT 19.503 19.873 19.521 19.927 ;
    END
  END w0_wmask_in[164]
  PIN w0_wmask_in[165]
    DIRECTION INPUT ;
    USE SIGNAL ;
    SHAPE ABUTMENT ;
    PORT
      LAYER M3 ;
      RECT 19.791 19.873 19.809 19.927 ;
    END
  END w0_wmask_in[165]
  PIN w0_wmask_in[166]
    DIRECTION INPUT ;
    USE SIGNAL ;
    SHAPE ABUTMENT ;
    PORT
      LAYER M3 ;
      RECT 20.079 19.873 20.097 19.927 ;
    END
  END w0_wmask_in[166]
  PIN w0_wmask_in[167]
    DIRECTION INPUT ;
    USE SIGNAL ;
    SHAPE ABUTMENT ;
    PORT
      LAYER M3 ;
      RECT 20.367 19.873 20.385 19.927 ;
    END
  END w0_wmask_in[167]
  PIN w0_wmask_in[168]
    DIRECTION INPUT ;
    USE SIGNAL ;
    SHAPE ABUTMENT ;
    PORT
      LAYER M3 ;
      RECT 20.655 19.873 20.673 19.927 ;
    END
  END w0_wmask_in[168]
  PIN w0_wmask_in[169]
    DIRECTION INPUT ;
    USE SIGNAL ;
    SHAPE ABUTMENT ;
    PORT
      LAYER M3 ;
      RECT 20.943 19.873 20.961 19.927 ;
    END
  END w0_wmask_in[169]
  PIN w0_wmask_in[170]
    DIRECTION INPUT ;
    USE SIGNAL ;
    SHAPE ABUTMENT ;
    PORT
      LAYER M3 ;
      RECT 21.231 19.873 21.249 19.927 ;
    END
  END w0_wmask_in[170]
  PIN w0_wmask_in[171]
    DIRECTION INPUT ;
    USE SIGNAL ;
    SHAPE ABUTMENT ;
    PORT
      LAYER M3 ;
      RECT 21.519 19.873 21.537 19.927 ;
    END
  END w0_wmask_in[171]
  PIN w0_wmask_in[172]
    DIRECTION INPUT ;
    USE SIGNAL ;
    SHAPE ABUTMENT ;
    PORT
      LAYER M3 ;
      RECT 21.807 19.873 21.825 19.927 ;
    END
  END w0_wmask_in[172]
  PIN w0_wmask_in[173]
    DIRECTION INPUT ;
    USE SIGNAL ;
    SHAPE ABUTMENT ;
    PORT
      LAYER M3 ;
      RECT 22.095 19.873 22.113 19.927 ;
    END
  END w0_wmask_in[173]
  PIN w0_wmask_in[174]
    DIRECTION INPUT ;
    USE SIGNAL ;
    SHAPE ABUTMENT ;
    PORT
      LAYER M3 ;
      RECT 22.383 19.873 22.401 19.927 ;
    END
  END w0_wmask_in[174]
  PIN w0_wmask_in[175]
    DIRECTION INPUT ;
    USE SIGNAL ;
    SHAPE ABUTMENT ;
    PORT
      LAYER M3 ;
      RECT 22.671 19.873 22.689 19.927 ;
    END
  END w0_wmask_in[175]
  PIN w0_wmask_in[176]
    DIRECTION INPUT ;
    USE SIGNAL ;
    SHAPE ABUTMENT ;
    PORT
      LAYER M3 ;
      RECT 22.959 19.873 22.977 19.927 ;
    END
  END w0_wmask_in[176]
  PIN w0_wmask_in[177]
    DIRECTION INPUT ;
    USE SIGNAL ;
    SHAPE ABUTMENT ;
    PORT
      LAYER M3 ;
      RECT 23.247 19.873 23.265 19.927 ;
    END
  END w0_wmask_in[177]
  PIN w0_wmask_in[178]
    DIRECTION INPUT ;
    USE SIGNAL ;
    SHAPE ABUTMENT ;
    PORT
      LAYER M3 ;
      RECT 23.535 19.873 23.553 19.927 ;
    END
  END w0_wmask_in[178]
  PIN w0_wmask_in[179]
    DIRECTION INPUT ;
    USE SIGNAL ;
    SHAPE ABUTMENT ;
    PORT
      LAYER M3 ;
      RECT 23.823 19.873 23.841 19.927 ;
    END
  END w0_wmask_in[179]
  PIN w0_wmask_in[180]
    DIRECTION INPUT ;
    USE SIGNAL ;
    SHAPE ABUTMENT ;
    PORT
      LAYER M3 ;
      RECT 24.111 19.873 24.129 19.927 ;
    END
  END w0_wmask_in[180]
  PIN w0_wmask_in[181]
    DIRECTION INPUT ;
    USE SIGNAL ;
    SHAPE ABUTMENT ;
    PORT
      LAYER M3 ;
      RECT 24.399 19.873 24.417 19.927 ;
    END
  END w0_wmask_in[181]
  PIN w0_wmask_in[182]
    DIRECTION INPUT ;
    USE SIGNAL ;
    SHAPE ABUTMENT ;
    PORT
      LAYER M3 ;
      RECT 24.687 19.873 24.705 19.927 ;
    END
  END w0_wmask_in[182]
  PIN w0_wmask_in[183]
    DIRECTION INPUT ;
    USE SIGNAL ;
    SHAPE ABUTMENT ;
    PORT
      LAYER M3 ;
      RECT 24.975 19.873 24.993 19.927 ;
    END
  END w0_wmask_in[183]
  PIN w0_wmask_in[184]
    DIRECTION INPUT ;
    USE SIGNAL ;
    SHAPE ABUTMENT ;
    PORT
      LAYER M3 ;
      RECT 25.263 19.873 25.281 19.927 ;
    END
  END w0_wmask_in[184]
  PIN w0_wmask_in[185]
    DIRECTION INPUT ;
    USE SIGNAL ;
    SHAPE ABUTMENT ;
    PORT
      LAYER M3 ;
      RECT 25.551 19.873 25.569 19.927 ;
    END
  END w0_wmask_in[185]
  PIN w0_wmask_in[186]
    DIRECTION INPUT ;
    USE SIGNAL ;
    SHAPE ABUTMENT ;
    PORT
      LAYER M3 ;
      RECT 25.839 19.873 25.857 19.927 ;
    END
  END w0_wmask_in[186]
  PIN w0_wmask_in[187]
    DIRECTION INPUT ;
    USE SIGNAL ;
    SHAPE ABUTMENT ;
    PORT
      LAYER M3 ;
      RECT 26.127 19.873 26.145 19.927 ;
    END
  END w0_wmask_in[187]
  PIN w0_wmask_in[188]
    DIRECTION INPUT ;
    USE SIGNAL ;
    SHAPE ABUTMENT ;
    PORT
      LAYER M3 ;
      RECT 26.415 19.873 26.433 19.927 ;
    END
  END w0_wmask_in[188]
  PIN w0_wmask_in[189]
    DIRECTION INPUT ;
    USE SIGNAL ;
    SHAPE ABUTMENT ;
    PORT
      LAYER M3 ;
      RECT 26.703 19.873 26.721 19.927 ;
    END
  END w0_wmask_in[189]
  PIN w0_wmask_in[190]
    DIRECTION INPUT ;
    USE SIGNAL ;
    SHAPE ABUTMENT ;
    PORT
      LAYER M3 ;
      RECT 26.991 19.873 27.009 19.927 ;
    END
  END w0_wmask_in[190]
  PIN w0_wmask_in[191]
    DIRECTION INPUT ;
    USE SIGNAL ;
    SHAPE ABUTMENT ;
    PORT
      LAYER M3 ;
      RECT 27.279 19.873 27.297 19.927 ;
    END
  END w0_wmask_in[191]
  PIN w0_wmask_in[192]
    DIRECTION INPUT ;
    USE SIGNAL ;
    SHAPE ABUTMENT ;
    PORT
      LAYER M3 ;
      RECT 27.567 19.873 27.585 19.927 ;
    END
  END w0_wmask_in[192]
  PIN w0_wd_in[0]
    DIRECTION INPUT ;
    USE SIGNAL ;
    SHAPE ABUTMENT ;
    PORT
      LAYER M4 ;
      RECT 0.000 7.332 0.072 7.356 ;
    END
  END w0_wd_in[0]
  PIN w0_wd_in[1]
    DIRECTION INPUT ;
    USE SIGNAL ;
    SHAPE ABUTMENT ;
    PORT
      LAYER M4 ;
      RECT 0.000 7.476 0.072 7.500 ;
    END
  END w0_wd_in[1]
  PIN w0_wd_in[2]
    DIRECTION INPUT ;
    USE SIGNAL ;
    SHAPE ABUTMENT ;
    PORT
      LAYER M4 ;
      RECT 0.000 7.620 0.072 7.644 ;
    END
  END w0_wd_in[2]
  PIN w0_wd_in[3]
    DIRECTION INPUT ;
    USE SIGNAL ;
    SHAPE ABUTMENT ;
    PORT
      LAYER M4 ;
      RECT 0.000 7.764 0.072 7.788 ;
    END
  END w0_wd_in[3]
  PIN w0_wd_in[4]
    DIRECTION INPUT ;
    USE SIGNAL ;
    SHAPE ABUTMENT ;
    PORT
      LAYER M4 ;
      RECT 0.000 7.908 0.072 7.932 ;
    END
  END w0_wd_in[4]
  PIN w0_wd_in[5]
    DIRECTION INPUT ;
    USE SIGNAL ;
    SHAPE ABUTMENT ;
    PORT
      LAYER M4 ;
      RECT 0.000 8.052 0.072 8.076 ;
    END
  END w0_wd_in[5]
  PIN w0_wd_in[6]
    DIRECTION INPUT ;
    USE SIGNAL ;
    SHAPE ABUTMENT ;
    PORT
      LAYER M4 ;
      RECT 0.000 8.196 0.072 8.220 ;
    END
  END w0_wd_in[6]
  PIN w0_wd_in[7]
    DIRECTION INPUT ;
    USE SIGNAL ;
    SHAPE ABUTMENT ;
    PORT
      LAYER M4 ;
      RECT 0.000 8.340 0.072 8.364 ;
    END
  END w0_wd_in[7]
  PIN w0_wd_in[8]
    DIRECTION INPUT ;
    USE SIGNAL ;
    SHAPE ABUTMENT ;
    PORT
      LAYER M4 ;
      RECT 0.000 8.484 0.072 8.508 ;
    END
  END w0_wd_in[8]
  PIN w0_wd_in[9]
    DIRECTION INPUT ;
    USE SIGNAL ;
    SHAPE ABUTMENT ;
    PORT
      LAYER M4 ;
      RECT 0.000 8.628 0.072 8.652 ;
    END
  END w0_wd_in[9]
  PIN w0_wd_in[10]
    DIRECTION INPUT ;
    USE SIGNAL ;
    SHAPE ABUTMENT ;
    PORT
      LAYER M4 ;
      RECT 0.000 8.772 0.072 8.796 ;
    END
  END w0_wd_in[10]
  PIN w0_wd_in[11]
    DIRECTION INPUT ;
    USE SIGNAL ;
    SHAPE ABUTMENT ;
    PORT
      LAYER M4 ;
      RECT 0.000 8.916 0.072 8.940 ;
    END
  END w0_wd_in[11]
  PIN w0_wd_in[12]
    DIRECTION INPUT ;
    USE SIGNAL ;
    SHAPE ABUTMENT ;
    PORT
      LAYER M4 ;
      RECT 0.000 9.060 0.072 9.084 ;
    END
  END w0_wd_in[12]
  PIN w0_wd_in[13]
    DIRECTION INPUT ;
    USE SIGNAL ;
    SHAPE ABUTMENT ;
    PORT
      LAYER M4 ;
      RECT 0.000 9.204 0.072 9.228 ;
    END
  END w0_wd_in[13]
  PIN w0_wd_in[14]
    DIRECTION INPUT ;
    USE SIGNAL ;
    SHAPE ABUTMENT ;
    PORT
      LAYER M4 ;
      RECT 0.000 9.348 0.072 9.372 ;
    END
  END w0_wd_in[14]
  PIN w0_wd_in[15]
    DIRECTION INPUT ;
    USE SIGNAL ;
    SHAPE ABUTMENT ;
    PORT
      LAYER M4 ;
      RECT 0.000 9.492 0.072 9.516 ;
    END
  END w0_wd_in[15]
  PIN w0_wd_in[16]
    DIRECTION INPUT ;
    USE SIGNAL ;
    SHAPE ABUTMENT ;
    PORT
      LAYER M4 ;
      RECT 0.000 9.636 0.072 9.660 ;
    END
  END w0_wd_in[16]
  PIN w0_wd_in[17]
    DIRECTION INPUT ;
    USE SIGNAL ;
    SHAPE ABUTMENT ;
    PORT
      LAYER M4 ;
      RECT 0.000 9.780 0.072 9.804 ;
    END
  END w0_wd_in[17]
  PIN w0_wd_in[18]
    DIRECTION INPUT ;
    USE SIGNAL ;
    SHAPE ABUTMENT ;
    PORT
      LAYER M4 ;
      RECT 0.000 9.924 0.072 9.948 ;
    END
  END w0_wd_in[18]
  PIN w0_wd_in[19]
    DIRECTION INPUT ;
    USE SIGNAL ;
    SHAPE ABUTMENT ;
    PORT
      LAYER M4 ;
      RECT 0.000 10.068 0.072 10.092 ;
    END
  END w0_wd_in[19]
  PIN w0_wd_in[20]
    DIRECTION INPUT ;
    USE SIGNAL ;
    SHAPE ABUTMENT ;
    PORT
      LAYER M4 ;
      RECT 0.000 10.212 0.072 10.236 ;
    END
  END w0_wd_in[20]
  PIN w0_wd_in[21]
    DIRECTION INPUT ;
    USE SIGNAL ;
    SHAPE ABUTMENT ;
    PORT
      LAYER M4 ;
      RECT 0.000 10.356 0.072 10.380 ;
    END
  END w0_wd_in[21]
  PIN w0_wd_in[22]
    DIRECTION INPUT ;
    USE SIGNAL ;
    SHAPE ABUTMENT ;
    PORT
      LAYER M4 ;
      RECT 0.000 10.500 0.072 10.524 ;
    END
  END w0_wd_in[22]
  PIN w0_wd_in[23]
    DIRECTION INPUT ;
    USE SIGNAL ;
    SHAPE ABUTMENT ;
    PORT
      LAYER M4 ;
      RECT 0.000 10.644 0.072 10.668 ;
    END
  END w0_wd_in[23]
  PIN w0_wd_in[24]
    DIRECTION INPUT ;
    USE SIGNAL ;
    SHAPE ABUTMENT ;
    PORT
      LAYER M4 ;
      RECT 0.000 10.788 0.072 10.812 ;
    END
  END w0_wd_in[24]
  PIN w0_wd_in[25]
    DIRECTION INPUT ;
    USE SIGNAL ;
    SHAPE ABUTMENT ;
    PORT
      LAYER M4 ;
      RECT 0.000 10.932 0.072 10.956 ;
    END
  END w0_wd_in[25]
  PIN w0_wd_in[26]
    DIRECTION INPUT ;
    USE SIGNAL ;
    SHAPE ABUTMENT ;
    PORT
      LAYER M4 ;
      RECT 0.000 11.076 0.072 11.100 ;
    END
  END w0_wd_in[26]
  PIN w0_wd_in[27]
    DIRECTION INPUT ;
    USE SIGNAL ;
    SHAPE ABUTMENT ;
    PORT
      LAYER M4 ;
      RECT 0.000 11.220 0.072 11.244 ;
    END
  END w0_wd_in[27]
  PIN w0_wd_in[28]
    DIRECTION INPUT ;
    USE SIGNAL ;
    SHAPE ABUTMENT ;
    PORT
      LAYER M4 ;
      RECT 0.000 11.364 0.072 11.388 ;
    END
  END w0_wd_in[28]
  PIN w0_wd_in[29]
    DIRECTION INPUT ;
    USE SIGNAL ;
    SHAPE ABUTMENT ;
    PORT
      LAYER M4 ;
      RECT 0.000 11.508 0.072 11.532 ;
    END
  END w0_wd_in[29]
  PIN w0_wd_in[30]
    DIRECTION INPUT ;
    USE SIGNAL ;
    SHAPE ABUTMENT ;
    PORT
      LAYER M4 ;
      RECT 0.000 11.652 0.072 11.676 ;
    END
  END w0_wd_in[30]
  PIN w0_wd_in[31]
    DIRECTION INPUT ;
    USE SIGNAL ;
    SHAPE ABUTMENT ;
    PORT
      LAYER M4 ;
      RECT 0.000 11.796 0.072 11.820 ;
    END
  END w0_wd_in[31]
  PIN w0_wd_in[32]
    DIRECTION INPUT ;
    USE SIGNAL ;
    SHAPE ABUTMENT ;
    PORT
      LAYER M4 ;
      RECT 0.000 11.940 0.072 11.964 ;
    END
  END w0_wd_in[32]
  PIN w0_wd_in[33]
    DIRECTION INPUT ;
    USE SIGNAL ;
    SHAPE ABUTMENT ;
    PORT
      LAYER M4 ;
      RECT 0.000 12.084 0.072 12.108 ;
    END
  END w0_wd_in[33]
  PIN w0_wd_in[34]
    DIRECTION INPUT ;
    USE SIGNAL ;
    SHAPE ABUTMENT ;
    PORT
      LAYER M4 ;
      RECT 0.000 12.228 0.072 12.252 ;
    END
  END w0_wd_in[34]
  PIN w0_wd_in[35]
    DIRECTION INPUT ;
    USE SIGNAL ;
    SHAPE ABUTMENT ;
    PORT
      LAYER M4 ;
      RECT 0.000 12.372 0.072 12.396 ;
    END
  END w0_wd_in[35]
  PIN w0_wd_in[36]
    DIRECTION INPUT ;
    USE SIGNAL ;
    SHAPE ABUTMENT ;
    PORT
      LAYER M4 ;
      RECT 0.000 12.516 0.072 12.540 ;
    END
  END w0_wd_in[36]
  PIN w0_wd_in[37]
    DIRECTION INPUT ;
    USE SIGNAL ;
    SHAPE ABUTMENT ;
    PORT
      LAYER M4 ;
      RECT 0.000 12.660 0.072 12.684 ;
    END
  END w0_wd_in[37]
  PIN w0_wd_in[38]
    DIRECTION INPUT ;
    USE SIGNAL ;
    SHAPE ABUTMENT ;
    PORT
      LAYER M4 ;
      RECT 0.000 12.804 0.072 12.828 ;
    END
  END w0_wd_in[38]
  PIN w0_wd_in[39]
    DIRECTION INPUT ;
    USE SIGNAL ;
    SHAPE ABUTMENT ;
    PORT
      LAYER M4 ;
      RECT 0.000 12.948 0.072 12.972 ;
    END
  END w0_wd_in[39]
  PIN w0_wd_in[40]
    DIRECTION INPUT ;
    USE SIGNAL ;
    SHAPE ABUTMENT ;
    PORT
      LAYER M4 ;
      RECT 0.000 13.092 0.072 13.116 ;
    END
  END w0_wd_in[40]
  PIN w0_wd_in[41]
    DIRECTION INPUT ;
    USE SIGNAL ;
    SHAPE ABUTMENT ;
    PORT
      LAYER M4 ;
      RECT 0.000 13.236 0.072 13.260 ;
    END
  END w0_wd_in[41]
  PIN w0_wd_in[42]
    DIRECTION INPUT ;
    USE SIGNAL ;
    SHAPE ABUTMENT ;
    PORT
      LAYER M4 ;
      RECT 0.000 13.380 0.072 13.404 ;
    END
  END w0_wd_in[42]
  PIN w0_wd_in[43]
    DIRECTION INPUT ;
    USE SIGNAL ;
    SHAPE ABUTMENT ;
    PORT
      LAYER M4 ;
      RECT 0.000 13.524 0.072 13.548 ;
    END
  END w0_wd_in[43]
  PIN w0_wd_in[44]
    DIRECTION INPUT ;
    USE SIGNAL ;
    SHAPE ABUTMENT ;
    PORT
      LAYER M4 ;
      RECT 0.000 13.668 0.072 13.692 ;
    END
  END w0_wd_in[44]
  PIN w0_wd_in[45]
    DIRECTION INPUT ;
    USE SIGNAL ;
    SHAPE ABUTMENT ;
    PORT
      LAYER M4 ;
      RECT 0.000 13.812 0.072 13.836 ;
    END
  END w0_wd_in[45]
  PIN w0_wd_in[46]
    DIRECTION INPUT ;
    USE SIGNAL ;
    SHAPE ABUTMENT ;
    PORT
      LAYER M4 ;
      RECT 0.000 13.956 0.072 13.980 ;
    END
  END w0_wd_in[46]
  PIN w0_wd_in[47]
    DIRECTION INPUT ;
    USE SIGNAL ;
    SHAPE ABUTMENT ;
    PORT
      LAYER M4 ;
      RECT 0.000 14.100 0.072 14.124 ;
    END
  END w0_wd_in[47]
  PIN w0_wd_in[48]
    DIRECTION INPUT ;
    USE SIGNAL ;
    SHAPE ABUTMENT ;
    PORT
      LAYER M4 ;
      RECT 0.000 14.244 0.072 14.268 ;
    END
  END w0_wd_in[48]
  PIN w0_wd_in[49]
    DIRECTION INPUT ;
    USE SIGNAL ;
    SHAPE ABUTMENT ;
    PORT
      LAYER M4 ;
      RECT 61.460 7.188 61.532 7.212 ;
    END
  END w0_wd_in[49]
  PIN w0_wd_in[50]
    DIRECTION INPUT ;
    USE SIGNAL ;
    SHAPE ABUTMENT ;
    PORT
      LAYER M4 ;
      RECT 61.460 7.332 61.532 7.356 ;
    END
  END w0_wd_in[50]
  PIN w0_wd_in[51]
    DIRECTION INPUT ;
    USE SIGNAL ;
    SHAPE ABUTMENT ;
    PORT
      LAYER M4 ;
      RECT 61.460 7.476 61.532 7.500 ;
    END
  END w0_wd_in[51]
  PIN w0_wd_in[52]
    DIRECTION INPUT ;
    USE SIGNAL ;
    SHAPE ABUTMENT ;
    PORT
      LAYER M4 ;
      RECT 61.460 7.620 61.532 7.644 ;
    END
  END w0_wd_in[52]
  PIN w0_wd_in[53]
    DIRECTION INPUT ;
    USE SIGNAL ;
    SHAPE ABUTMENT ;
    PORT
      LAYER M4 ;
      RECT 61.460 7.764 61.532 7.788 ;
    END
  END w0_wd_in[53]
  PIN w0_wd_in[54]
    DIRECTION INPUT ;
    USE SIGNAL ;
    SHAPE ABUTMENT ;
    PORT
      LAYER M4 ;
      RECT 61.460 7.908 61.532 7.932 ;
    END
  END w0_wd_in[54]
  PIN w0_wd_in[55]
    DIRECTION INPUT ;
    USE SIGNAL ;
    SHAPE ABUTMENT ;
    PORT
      LAYER M4 ;
      RECT 61.460 8.052 61.532 8.076 ;
    END
  END w0_wd_in[55]
  PIN w0_wd_in[56]
    DIRECTION INPUT ;
    USE SIGNAL ;
    SHAPE ABUTMENT ;
    PORT
      LAYER M4 ;
      RECT 61.460 8.196 61.532 8.220 ;
    END
  END w0_wd_in[56]
  PIN w0_wd_in[57]
    DIRECTION INPUT ;
    USE SIGNAL ;
    SHAPE ABUTMENT ;
    PORT
      LAYER M4 ;
      RECT 61.460 8.340 61.532 8.364 ;
    END
  END w0_wd_in[57]
  PIN w0_wd_in[58]
    DIRECTION INPUT ;
    USE SIGNAL ;
    SHAPE ABUTMENT ;
    PORT
      LAYER M4 ;
      RECT 61.460 8.484 61.532 8.508 ;
    END
  END w0_wd_in[58]
  PIN w0_wd_in[59]
    DIRECTION INPUT ;
    USE SIGNAL ;
    SHAPE ABUTMENT ;
    PORT
      LAYER M4 ;
      RECT 61.460 8.628 61.532 8.652 ;
    END
  END w0_wd_in[59]
  PIN w0_wd_in[60]
    DIRECTION INPUT ;
    USE SIGNAL ;
    SHAPE ABUTMENT ;
    PORT
      LAYER M4 ;
      RECT 61.460 8.772 61.532 8.796 ;
    END
  END w0_wd_in[60]
  PIN w0_wd_in[61]
    DIRECTION INPUT ;
    USE SIGNAL ;
    SHAPE ABUTMENT ;
    PORT
      LAYER M4 ;
      RECT 61.460 8.916 61.532 8.940 ;
    END
  END w0_wd_in[61]
  PIN w0_wd_in[62]
    DIRECTION INPUT ;
    USE SIGNAL ;
    SHAPE ABUTMENT ;
    PORT
      LAYER M4 ;
      RECT 61.460 9.060 61.532 9.084 ;
    END
  END w0_wd_in[62]
  PIN w0_wd_in[63]
    DIRECTION INPUT ;
    USE SIGNAL ;
    SHAPE ABUTMENT ;
    PORT
      LAYER M4 ;
      RECT 61.460 9.204 61.532 9.228 ;
    END
  END w0_wd_in[63]
  PIN w0_wd_in[64]
    DIRECTION INPUT ;
    USE SIGNAL ;
    SHAPE ABUTMENT ;
    PORT
      LAYER M4 ;
      RECT 61.460 9.348 61.532 9.372 ;
    END
  END w0_wd_in[64]
  PIN w0_wd_in[65]
    DIRECTION INPUT ;
    USE SIGNAL ;
    SHAPE ABUTMENT ;
    PORT
      LAYER M4 ;
      RECT 61.460 9.492 61.532 9.516 ;
    END
  END w0_wd_in[65]
  PIN w0_wd_in[66]
    DIRECTION INPUT ;
    USE SIGNAL ;
    SHAPE ABUTMENT ;
    PORT
      LAYER M4 ;
      RECT 61.460 9.636 61.532 9.660 ;
    END
  END w0_wd_in[66]
  PIN w0_wd_in[67]
    DIRECTION INPUT ;
    USE SIGNAL ;
    SHAPE ABUTMENT ;
    PORT
      LAYER M4 ;
      RECT 61.460 9.780 61.532 9.804 ;
    END
  END w0_wd_in[67]
  PIN w0_wd_in[68]
    DIRECTION INPUT ;
    USE SIGNAL ;
    SHAPE ABUTMENT ;
    PORT
      LAYER M4 ;
      RECT 61.460 9.924 61.532 9.948 ;
    END
  END w0_wd_in[68]
  PIN w0_wd_in[69]
    DIRECTION INPUT ;
    USE SIGNAL ;
    SHAPE ABUTMENT ;
    PORT
      LAYER M4 ;
      RECT 61.460 10.068 61.532 10.092 ;
    END
  END w0_wd_in[69]
  PIN w0_wd_in[70]
    DIRECTION INPUT ;
    USE SIGNAL ;
    SHAPE ABUTMENT ;
    PORT
      LAYER M4 ;
      RECT 61.460 10.212 61.532 10.236 ;
    END
  END w0_wd_in[70]
  PIN w0_wd_in[71]
    DIRECTION INPUT ;
    USE SIGNAL ;
    SHAPE ABUTMENT ;
    PORT
      LAYER M4 ;
      RECT 61.460 10.356 61.532 10.380 ;
    END
  END w0_wd_in[71]
  PIN w0_wd_in[72]
    DIRECTION INPUT ;
    USE SIGNAL ;
    SHAPE ABUTMENT ;
    PORT
      LAYER M4 ;
      RECT 61.460 10.500 61.532 10.524 ;
    END
  END w0_wd_in[72]
  PIN w0_wd_in[73]
    DIRECTION INPUT ;
    USE SIGNAL ;
    SHAPE ABUTMENT ;
    PORT
      LAYER M4 ;
      RECT 61.460 10.644 61.532 10.668 ;
    END
  END w0_wd_in[73]
  PIN w0_wd_in[74]
    DIRECTION INPUT ;
    USE SIGNAL ;
    SHAPE ABUTMENT ;
    PORT
      LAYER M4 ;
      RECT 61.460 10.788 61.532 10.812 ;
    END
  END w0_wd_in[74]
  PIN w0_wd_in[75]
    DIRECTION INPUT ;
    USE SIGNAL ;
    SHAPE ABUTMENT ;
    PORT
      LAYER M4 ;
      RECT 61.460 10.932 61.532 10.956 ;
    END
  END w0_wd_in[75]
  PIN w0_wd_in[76]
    DIRECTION INPUT ;
    USE SIGNAL ;
    SHAPE ABUTMENT ;
    PORT
      LAYER M4 ;
      RECT 61.460 11.076 61.532 11.100 ;
    END
  END w0_wd_in[76]
  PIN w0_wd_in[77]
    DIRECTION INPUT ;
    USE SIGNAL ;
    SHAPE ABUTMENT ;
    PORT
      LAYER M4 ;
      RECT 61.460 11.220 61.532 11.244 ;
    END
  END w0_wd_in[77]
  PIN w0_wd_in[78]
    DIRECTION INPUT ;
    USE SIGNAL ;
    SHAPE ABUTMENT ;
    PORT
      LAYER M4 ;
      RECT 61.460 11.364 61.532 11.388 ;
    END
  END w0_wd_in[78]
  PIN w0_wd_in[79]
    DIRECTION INPUT ;
    USE SIGNAL ;
    SHAPE ABUTMENT ;
    PORT
      LAYER M4 ;
      RECT 61.460 11.508 61.532 11.532 ;
    END
  END w0_wd_in[79]
  PIN w0_wd_in[80]
    DIRECTION INPUT ;
    USE SIGNAL ;
    SHAPE ABUTMENT ;
    PORT
      LAYER M4 ;
      RECT 61.460 11.652 61.532 11.676 ;
    END
  END w0_wd_in[80]
  PIN w0_wd_in[81]
    DIRECTION INPUT ;
    USE SIGNAL ;
    SHAPE ABUTMENT ;
    PORT
      LAYER M4 ;
      RECT 61.460 11.796 61.532 11.820 ;
    END
  END w0_wd_in[81]
  PIN w0_wd_in[82]
    DIRECTION INPUT ;
    USE SIGNAL ;
    SHAPE ABUTMENT ;
    PORT
      LAYER M4 ;
      RECT 61.460 11.940 61.532 11.964 ;
    END
  END w0_wd_in[82]
  PIN w0_wd_in[83]
    DIRECTION INPUT ;
    USE SIGNAL ;
    SHAPE ABUTMENT ;
    PORT
      LAYER M4 ;
      RECT 61.460 12.084 61.532 12.108 ;
    END
  END w0_wd_in[83]
  PIN w0_wd_in[84]
    DIRECTION INPUT ;
    USE SIGNAL ;
    SHAPE ABUTMENT ;
    PORT
      LAYER M4 ;
      RECT 61.460 12.228 61.532 12.252 ;
    END
  END w0_wd_in[84]
  PIN w0_wd_in[85]
    DIRECTION INPUT ;
    USE SIGNAL ;
    SHAPE ABUTMENT ;
    PORT
      LAYER M4 ;
      RECT 61.460 12.372 61.532 12.396 ;
    END
  END w0_wd_in[85]
  PIN w0_wd_in[86]
    DIRECTION INPUT ;
    USE SIGNAL ;
    SHAPE ABUTMENT ;
    PORT
      LAYER M4 ;
      RECT 61.460 12.516 61.532 12.540 ;
    END
  END w0_wd_in[86]
  PIN w0_wd_in[87]
    DIRECTION INPUT ;
    USE SIGNAL ;
    SHAPE ABUTMENT ;
    PORT
      LAYER M4 ;
      RECT 61.460 12.660 61.532 12.684 ;
    END
  END w0_wd_in[87]
  PIN w0_wd_in[88]
    DIRECTION INPUT ;
    USE SIGNAL ;
    SHAPE ABUTMENT ;
    PORT
      LAYER M4 ;
      RECT 61.460 12.804 61.532 12.828 ;
    END
  END w0_wd_in[88]
  PIN w0_wd_in[89]
    DIRECTION INPUT ;
    USE SIGNAL ;
    SHAPE ABUTMENT ;
    PORT
      LAYER M4 ;
      RECT 61.460 12.948 61.532 12.972 ;
    END
  END w0_wd_in[89]
  PIN w0_wd_in[90]
    DIRECTION INPUT ;
    USE SIGNAL ;
    SHAPE ABUTMENT ;
    PORT
      LAYER M4 ;
      RECT 61.460 13.092 61.532 13.116 ;
    END
  END w0_wd_in[90]
  PIN w0_wd_in[91]
    DIRECTION INPUT ;
    USE SIGNAL ;
    SHAPE ABUTMENT ;
    PORT
      LAYER M4 ;
      RECT 61.460 13.236 61.532 13.260 ;
    END
  END w0_wd_in[91]
  PIN w0_wd_in[92]
    DIRECTION INPUT ;
    USE SIGNAL ;
    SHAPE ABUTMENT ;
    PORT
      LAYER M4 ;
      RECT 61.460 13.380 61.532 13.404 ;
    END
  END w0_wd_in[92]
  PIN w0_wd_in[93]
    DIRECTION INPUT ;
    USE SIGNAL ;
    SHAPE ABUTMENT ;
    PORT
      LAYER M4 ;
      RECT 61.460 13.524 61.532 13.548 ;
    END
  END w0_wd_in[93]
  PIN w0_wd_in[94]
    DIRECTION INPUT ;
    USE SIGNAL ;
    SHAPE ABUTMENT ;
    PORT
      LAYER M4 ;
      RECT 61.460 13.668 61.532 13.692 ;
    END
  END w0_wd_in[94]
  PIN w0_wd_in[95]
    DIRECTION INPUT ;
    USE SIGNAL ;
    SHAPE ABUTMENT ;
    PORT
      LAYER M4 ;
      RECT 61.460 13.812 61.532 13.836 ;
    END
  END w0_wd_in[95]
  PIN w0_wd_in[96]
    DIRECTION INPUT ;
    USE SIGNAL ;
    SHAPE ABUTMENT ;
    PORT
      LAYER M4 ;
      RECT 61.460 13.956 61.532 13.980 ;
    END
  END w0_wd_in[96]
  PIN w0_wd_in[97]
    DIRECTION OUTPUT ;
    USE SIGNAL ;
    SHAPE ABUTMENT ;
    PORT
      LAYER M3 ;
      RECT 0.207 0.000 0.225 0.054 ;
    END
  END w0_wd_in[97]
  PIN w0_wd_in[98]
    DIRECTION OUTPUT ;
    USE SIGNAL ;
    SHAPE ABUTMENT ;
    PORT
      LAYER M3 ;
      RECT 0.495 0.000 0.513 0.054 ;
    END
  END w0_wd_in[98]
  PIN w0_wd_in[99]
    DIRECTION OUTPUT ;
    USE SIGNAL ;
    SHAPE ABUTMENT ;
    PORT
      LAYER M3 ;
      RECT 0.783 0.000 0.801 0.054 ;
    END
  END w0_wd_in[99]
  PIN w0_wd_in[100]
    DIRECTION OUTPUT ;
    USE SIGNAL ;
    SHAPE ABUTMENT ;
    PORT
      LAYER M3 ;
      RECT 1.071 0.000 1.089 0.054 ;
    END
  END w0_wd_in[100]
  PIN w0_wd_in[101]
    DIRECTION OUTPUT ;
    USE SIGNAL ;
    SHAPE ABUTMENT ;
    PORT
      LAYER M3 ;
      RECT 1.359 0.000 1.377 0.054 ;
    END
  END w0_wd_in[101]
  PIN w0_wd_in[102]
    DIRECTION OUTPUT ;
    USE SIGNAL ;
    SHAPE ABUTMENT ;
    PORT
      LAYER M3 ;
      RECT 1.647 0.000 1.665 0.054 ;
    END
  END w0_wd_in[102]
  PIN w0_wd_in[103]
    DIRECTION OUTPUT ;
    USE SIGNAL ;
    SHAPE ABUTMENT ;
    PORT
      LAYER M3 ;
      RECT 1.935 0.000 1.953 0.054 ;
    END
  END w0_wd_in[103]
  PIN w0_wd_in[104]
    DIRECTION OUTPUT ;
    USE SIGNAL ;
    SHAPE ABUTMENT ;
    PORT
      LAYER M3 ;
      RECT 2.223 0.000 2.241 0.054 ;
    END
  END w0_wd_in[104]
  PIN w0_wd_in[105]
    DIRECTION OUTPUT ;
    USE SIGNAL ;
    SHAPE ABUTMENT ;
    PORT
      LAYER M3 ;
      RECT 2.511 0.000 2.529 0.054 ;
    END
  END w0_wd_in[105]
  PIN w0_wd_in[106]
    DIRECTION OUTPUT ;
    USE SIGNAL ;
    SHAPE ABUTMENT ;
    PORT
      LAYER M3 ;
      RECT 2.799 0.000 2.817 0.054 ;
    END
  END w0_wd_in[106]
  PIN w0_wd_in[107]
    DIRECTION OUTPUT ;
    USE SIGNAL ;
    SHAPE ABUTMENT ;
    PORT
      LAYER M3 ;
      RECT 3.087 0.000 3.105 0.054 ;
    END
  END w0_wd_in[107]
  PIN w0_wd_in[108]
    DIRECTION OUTPUT ;
    USE SIGNAL ;
    SHAPE ABUTMENT ;
    PORT
      LAYER M3 ;
      RECT 3.375 0.000 3.393 0.054 ;
    END
  END w0_wd_in[108]
  PIN w0_wd_in[109]
    DIRECTION OUTPUT ;
    USE SIGNAL ;
    SHAPE ABUTMENT ;
    PORT
      LAYER M3 ;
      RECT 3.663 0.000 3.681 0.054 ;
    END
  END w0_wd_in[109]
  PIN w0_wd_in[110]
    DIRECTION OUTPUT ;
    USE SIGNAL ;
    SHAPE ABUTMENT ;
    PORT
      LAYER M3 ;
      RECT 3.951 0.000 3.969 0.054 ;
    END
  END w0_wd_in[110]
  PIN w0_wd_in[111]
    DIRECTION OUTPUT ;
    USE SIGNAL ;
    SHAPE ABUTMENT ;
    PORT
      LAYER M3 ;
      RECT 4.239 0.000 4.257 0.054 ;
    END
  END w0_wd_in[111]
  PIN w0_wd_in[112]
    DIRECTION OUTPUT ;
    USE SIGNAL ;
    SHAPE ABUTMENT ;
    PORT
      LAYER M3 ;
      RECT 4.527 0.000 4.545 0.054 ;
    END
  END w0_wd_in[112]
  PIN w0_wd_in[113]
    DIRECTION OUTPUT ;
    USE SIGNAL ;
    SHAPE ABUTMENT ;
    PORT
      LAYER M3 ;
      RECT 4.815 0.000 4.833 0.054 ;
    END
  END w0_wd_in[113]
  PIN w0_wd_in[114]
    DIRECTION OUTPUT ;
    USE SIGNAL ;
    SHAPE ABUTMENT ;
    PORT
      LAYER M3 ;
      RECT 5.103 0.000 5.121 0.054 ;
    END
  END w0_wd_in[114]
  PIN w0_wd_in[115]
    DIRECTION OUTPUT ;
    USE SIGNAL ;
    SHAPE ABUTMENT ;
    PORT
      LAYER M3 ;
      RECT 5.391 0.000 5.409 0.054 ;
    END
  END w0_wd_in[115]
  PIN w0_wd_in[116]
    DIRECTION OUTPUT ;
    USE SIGNAL ;
    SHAPE ABUTMENT ;
    PORT
      LAYER M3 ;
      RECT 5.679 0.000 5.697 0.054 ;
    END
  END w0_wd_in[116]
  PIN w0_wd_in[117]
    DIRECTION OUTPUT ;
    USE SIGNAL ;
    SHAPE ABUTMENT ;
    PORT
      LAYER M3 ;
      RECT 5.967 0.000 5.985 0.054 ;
    END
  END w0_wd_in[117]
  PIN w0_wd_in[118]
    DIRECTION OUTPUT ;
    USE SIGNAL ;
    SHAPE ABUTMENT ;
    PORT
      LAYER M3 ;
      RECT 6.255 0.000 6.273 0.054 ;
    END
  END w0_wd_in[118]
  PIN w0_wd_in[119]
    DIRECTION OUTPUT ;
    USE SIGNAL ;
    SHAPE ABUTMENT ;
    PORT
      LAYER M3 ;
      RECT 6.543 0.000 6.561 0.054 ;
    END
  END w0_wd_in[119]
  PIN w0_wd_in[120]
    DIRECTION OUTPUT ;
    USE SIGNAL ;
    SHAPE ABUTMENT ;
    PORT
      LAYER M3 ;
      RECT 6.831 0.000 6.849 0.054 ;
    END
  END w0_wd_in[120]
  PIN w0_wd_in[121]
    DIRECTION OUTPUT ;
    USE SIGNAL ;
    SHAPE ABUTMENT ;
    PORT
      LAYER M3 ;
      RECT 7.119 0.000 7.137 0.054 ;
    END
  END w0_wd_in[121]
  PIN w0_wd_in[122]
    DIRECTION OUTPUT ;
    USE SIGNAL ;
    SHAPE ABUTMENT ;
    PORT
      LAYER M3 ;
      RECT 7.407 0.000 7.425 0.054 ;
    END
  END w0_wd_in[122]
  PIN w0_wd_in[123]
    DIRECTION OUTPUT ;
    USE SIGNAL ;
    SHAPE ABUTMENT ;
    PORT
      LAYER M3 ;
      RECT 7.695 0.000 7.713 0.054 ;
    END
  END w0_wd_in[123]
  PIN w0_wd_in[124]
    DIRECTION OUTPUT ;
    USE SIGNAL ;
    SHAPE ABUTMENT ;
    PORT
      LAYER M3 ;
      RECT 7.983 0.000 8.001 0.054 ;
    END
  END w0_wd_in[124]
  PIN w0_wd_in[125]
    DIRECTION OUTPUT ;
    USE SIGNAL ;
    SHAPE ABUTMENT ;
    PORT
      LAYER M3 ;
      RECT 8.271 0.000 8.289 0.054 ;
    END
  END w0_wd_in[125]
  PIN w0_wd_in[126]
    DIRECTION OUTPUT ;
    USE SIGNAL ;
    SHAPE ABUTMENT ;
    PORT
      LAYER M3 ;
      RECT 8.559 0.000 8.577 0.054 ;
    END
  END w0_wd_in[126]
  PIN w0_wd_in[127]
    DIRECTION OUTPUT ;
    USE SIGNAL ;
    SHAPE ABUTMENT ;
    PORT
      LAYER M3 ;
      RECT 8.847 0.000 8.865 0.054 ;
    END
  END w0_wd_in[127]
  PIN w0_wd_in[128]
    DIRECTION OUTPUT ;
    USE SIGNAL ;
    SHAPE ABUTMENT ;
    PORT
      LAYER M3 ;
      RECT 9.135 0.000 9.153 0.054 ;
    END
  END w0_wd_in[128]
  PIN w0_wd_in[129]
    DIRECTION OUTPUT ;
    USE SIGNAL ;
    SHAPE ABUTMENT ;
    PORT
      LAYER M3 ;
      RECT 9.423 0.000 9.441 0.054 ;
    END
  END w0_wd_in[129]
  PIN w0_wd_in[130]
    DIRECTION OUTPUT ;
    USE SIGNAL ;
    SHAPE ABUTMENT ;
    PORT
      LAYER M3 ;
      RECT 9.711 0.000 9.729 0.054 ;
    END
  END w0_wd_in[130]
  PIN w0_wd_in[131]
    DIRECTION OUTPUT ;
    USE SIGNAL ;
    SHAPE ABUTMENT ;
    PORT
      LAYER M3 ;
      RECT 9.999 0.000 10.017 0.054 ;
    END
  END w0_wd_in[131]
  PIN w0_wd_in[132]
    DIRECTION OUTPUT ;
    USE SIGNAL ;
    SHAPE ABUTMENT ;
    PORT
      LAYER M3 ;
      RECT 10.287 0.000 10.305 0.054 ;
    END
  END w0_wd_in[132]
  PIN w0_wd_in[133]
    DIRECTION OUTPUT ;
    USE SIGNAL ;
    SHAPE ABUTMENT ;
    PORT
      LAYER M3 ;
      RECT 10.575 0.000 10.593 0.054 ;
    END
  END w0_wd_in[133]
  PIN w0_wd_in[134]
    DIRECTION OUTPUT ;
    USE SIGNAL ;
    SHAPE ABUTMENT ;
    PORT
      LAYER M3 ;
      RECT 10.863 0.000 10.881 0.054 ;
    END
  END w0_wd_in[134]
  PIN w0_wd_in[135]
    DIRECTION OUTPUT ;
    USE SIGNAL ;
    SHAPE ABUTMENT ;
    PORT
      LAYER M3 ;
      RECT 11.151 0.000 11.169 0.054 ;
    END
  END w0_wd_in[135]
  PIN w0_wd_in[136]
    DIRECTION OUTPUT ;
    USE SIGNAL ;
    SHAPE ABUTMENT ;
    PORT
      LAYER M3 ;
      RECT 11.439 0.000 11.457 0.054 ;
    END
  END w0_wd_in[136]
  PIN w0_wd_in[137]
    DIRECTION OUTPUT ;
    USE SIGNAL ;
    SHAPE ABUTMENT ;
    PORT
      LAYER M3 ;
      RECT 11.727 0.000 11.745 0.054 ;
    END
  END w0_wd_in[137]
  PIN w0_wd_in[138]
    DIRECTION OUTPUT ;
    USE SIGNAL ;
    SHAPE ABUTMENT ;
    PORT
      LAYER M3 ;
      RECT 12.015 0.000 12.033 0.054 ;
    END
  END w0_wd_in[138]
  PIN w0_wd_in[139]
    DIRECTION OUTPUT ;
    USE SIGNAL ;
    SHAPE ABUTMENT ;
    PORT
      LAYER M3 ;
      RECT 12.303 0.000 12.321 0.054 ;
    END
  END w0_wd_in[139]
  PIN w0_wd_in[140]
    DIRECTION OUTPUT ;
    USE SIGNAL ;
    SHAPE ABUTMENT ;
    PORT
      LAYER M3 ;
      RECT 12.591 0.000 12.609 0.054 ;
    END
  END w0_wd_in[140]
  PIN w0_wd_in[141]
    DIRECTION OUTPUT ;
    USE SIGNAL ;
    SHAPE ABUTMENT ;
    PORT
      LAYER M3 ;
      RECT 12.879 0.000 12.897 0.054 ;
    END
  END w0_wd_in[141]
  PIN w0_wd_in[142]
    DIRECTION OUTPUT ;
    USE SIGNAL ;
    SHAPE ABUTMENT ;
    PORT
      LAYER M3 ;
      RECT 13.167 0.000 13.185 0.054 ;
    END
  END w0_wd_in[142]
  PIN w0_wd_in[143]
    DIRECTION OUTPUT ;
    USE SIGNAL ;
    SHAPE ABUTMENT ;
    PORT
      LAYER M3 ;
      RECT 13.455 0.000 13.473 0.054 ;
    END
  END w0_wd_in[143]
  PIN w0_wd_in[144]
    DIRECTION OUTPUT ;
    USE SIGNAL ;
    SHAPE ABUTMENT ;
    PORT
      LAYER M3 ;
      RECT 13.743 0.000 13.761 0.054 ;
    END
  END w0_wd_in[144]
  PIN w0_wd_in[145]
    DIRECTION OUTPUT ;
    USE SIGNAL ;
    SHAPE ABUTMENT ;
    PORT
      LAYER M3 ;
      RECT 14.031 0.000 14.049 0.054 ;
    END
  END w0_wd_in[145]
  PIN w0_wd_in[146]
    DIRECTION OUTPUT ;
    USE SIGNAL ;
    SHAPE ABUTMENT ;
    PORT
      LAYER M3 ;
      RECT 14.319 0.000 14.337 0.054 ;
    END
  END w0_wd_in[146]
  PIN w0_wd_in[147]
    DIRECTION OUTPUT ;
    USE SIGNAL ;
    SHAPE ABUTMENT ;
    PORT
      LAYER M3 ;
      RECT 14.607 0.000 14.625 0.054 ;
    END
  END w0_wd_in[147]
  PIN w0_wd_in[148]
    DIRECTION OUTPUT ;
    USE SIGNAL ;
    SHAPE ABUTMENT ;
    PORT
      LAYER M3 ;
      RECT 14.895 0.000 14.913 0.054 ;
    END
  END w0_wd_in[148]
  PIN w0_wd_in[149]
    DIRECTION OUTPUT ;
    USE SIGNAL ;
    SHAPE ABUTMENT ;
    PORT
      LAYER M3 ;
      RECT 15.183 0.000 15.201 0.054 ;
    END
  END w0_wd_in[149]
  PIN w0_wd_in[150]
    DIRECTION OUTPUT ;
    USE SIGNAL ;
    SHAPE ABUTMENT ;
    PORT
      LAYER M3 ;
      RECT 15.471 0.000 15.489 0.054 ;
    END
  END w0_wd_in[150]
  PIN w0_wd_in[151]
    DIRECTION OUTPUT ;
    USE SIGNAL ;
    SHAPE ABUTMENT ;
    PORT
      LAYER M3 ;
      RECT 15.759 0.000 15.777 0.054 ;
    END
  END w0_wd_in[151]
  PIN w0_wd_in[152]
    DIRECTION OUTPUT ;
    USE SIGNAL ;
    SHAPE ABUTMENT ;
    PORT
      LAYER M3 ;
      RECT 16.047 0.000 16.065 0.054 ;
    END
  END w0_wd_in[152]
  PIN w0_wd_in[153]
    DIRECTION OUTPUT ;
    USE SIGNAL ;
    SHAPE ABUTMENT ;
    PORT
      LAYER M3 ;
      RECT 16.335 0.000 16.353 0.054 ;
    END
  END w0_wd_in[153]
  PIN w0_wd_in[154]
    DIRECTION OUTPUT ;
    USE SIGNAL ;
    SHAPE ABUTMENT ;
    PORT
      LAYER M3 ;
      RECT 16.623 0.000 16.641 0.054 ;
    END
  END w0_wd_in[154]
  PIN w0_wd_in[155]
    DIRECTION OUTPUT ;
    USE SIGNAL ;
    SHAPE ABUTMENT ;
    PORT
      LAYER M3 ;
      RECT 16.911 0.000 16.929 0.054 ;
    END
  END w0_wd_in[155]
  PIN w0_wd_in[156]
    DIRECTION OUTPUT ;
    USE SIGNAL ;
    SHAPE ABUTMENT ;
    PORT
      LAYER M3 ;
      RECT 17.199 0.000 17.217 0.054 ;
    END
  END w0_wd_in[156]
  PIN w0_wd_in[157]
    DIRECTION OUTPUT ;
    USE SIGNAL ;
    SHAPE ABUTMENT ;
    PORT
      LAYER M3 ;
      RECT 17.487 0.000 17.505 0.054 ;
    END
  END w0_wd_in[157]
  PIN w0_wd_in[158]
    DIRECTION OUTPUT ;
    USE SIGNAL ;
    SHAPE ABUTMENT ;
    PORT
      LAYER M3 ;
      RECT 17.775 0.000 17.793 0.054 ;
    END
  END w0_wd_in[158]
  PIN w0_wd_in[159]
    DIRECTION OUTPUT ;
    USE SIGNAL ;
    SHAPE ABUTMENT ;
    PORT
      LAYER M3 ;
      RECT 18.063 0.000 18.081 0.054 ;
    END
  END w0_wd_in[159]
  PIN w0_wd_in[160]
    DIRECTION OUTPUT ;
    USE SIGNAL ;
    SHAPE ABUTMENT ;
    PORT
      LAYER M3 ;
      RECT 18.351 0.000 18.369 0.054 ;
    END
  END w0_wd_in[160]
  PIN w0_wd_in[161]
    DIRECTION OUTPUT ;
    USE SIGNAL ;
    SHAPE ABUTMENT ;
    PORT
      LAYER M3 ;
      RECT 18.639 0.000 18.657 0.054 ;
    END
  END w0_wd_in[161]
  PIN w0_wd_in[162]
    DIRECTION OUTPUT ;
    USE SIGNAL ;
    SHAPE ABUTMENT ;
    PORT
      LAYER M3 ;
      RECT 18.927 0.000 18.945 0.054 ;
    END
  END w0_wd_in[162]
  PIN w0_wd_in[163]
    DIRECTION OUTPUT ;
    USE SIGNAL ;
    SHAPE ABUTMENT ;
    PORT
      LAYER M3 ;
      RECT 19.215 0.000 19.233 0.054 ;
    END
  END w0_wd_in[163]
  PIN w0_wd_in[164]
    DIRECTION OUTPUT ;
    USE SIGNAL ;
    SHAPE ABUTMENT ;
    PORT
      LAYER M3 ;
      RECT 19.503 0.000 19.521 0.054 ;
    END
  END w0_wd_in[164]
  PIN w0_wd_in[165]
    DIRECTION OUTPUT ;
    USE SIGNAL ;
    SHAPE ABUTMENT ;
    PORT
      LAYER M3 ;
      RECT 19.791 0.000 19.809 0.054 ;
    END
  END w0_wd_in[165]
  PIN w0_wd_in[166]
    DIRECTION OUTPUT ;
    USE SIGNAL ;
    SHAPE ABUTMENT ;
    PORT
      LAYER M3 ;
      RECT 20.079 0.000 20.097 0.054 ;
    END
  END w0_wd_in[166]
  PIN w0_wd_in[167]
    DIRECTION OUTPUT ;
    USE SIGNAL ;
    SHAPE ABUTMENT ;
    PORT
      LAYER M3 ;
      RECT 20.367 0.000 20.385 0.054 ;
    END
  END w0_wd_in[167]
  PIN w0_wd_in[168]
    DIRECTION OUTPUT ;
    USE SIGNAL ;
    SHAPE ABUTMENT ;
    PORT
      LAYER M3 ;
      RECT 20.655 0.000 20.673 0.054 ;
    END
  END w0_wd_in[168]
  PIN w0_wd_in[169]
    DIRECTION OUTPUT ;
    USE SIGNAL ;
    SHAPE ABUTMENT ;
    PORT
      LAYER M3 ;
      RECT 20.943 0.000 20.961 0.054 ;
    END
  END w0_wd_in[169]
  PIN w0_wd_in[170]
    DIRECTION OUTPUT ;
    USE SIGNAL ;
    SHAPE ABUTMENT ;
    PORT
      LAYER M3 ;
      RECT 21.231 0.000 21.249 0.054 ;
    END
  END w0_wd_in[170]
  PIN w0_wd_in[171]
    DIRECTION OUTPUT ;
    USE SIGNAL ;
    SHAPE ABUTMENT ;
    PORT
      LAYER M3 ;
      RECT 21.519 0.000 21.537 0.054 ;
    END
  END w0_wd_in[171]
  PIN w0_wd_in[172]
    DIRECTION OUTPUT ;
    USE SIGNAL ;
    SHAPE ABUTMENT ;
    PORT
      LAYER M3 ;
      RECT 21.807 0.000 21.825 0.054 ;
    END
  END w0_wd_in[172]
  PIN w0_wd_in[173]
    DIRECTION OUTPUT ;
    USE SIGNAL ;
    SHAPE ABUTMENT ;
    PORT
      LAYER M3 ;
      RECT 22.095 0.000 22.113 0.054 ;
    END
  END w0_wd_in[173]
  PIN w0_wd_in[174]
    DIRECTION OUTPUT ;
    USE SIGNAL ;
    SHAPE ABUTMENT ;
    PORT
      LAYER M3 ;
      RECT 22.383 0.000 22.401 0.054 ;
    END
  END w0_wd_in[174]
  PIN w0_wd_in[175]
    DIRECTION OUTPUT ;
    USE SIGNAL ;
    SHAPE ABUTMENT ;
    PORT
      LAYER M3 ;
      RECT 22.671 0.000 22.689 0.054 ;
    END
  END w0_wd_in[175]
  PIN w0_wd_in[176]
    DIRECTION OUTPUT ;
    USE SIGNAL ;
    SHAPE ABUTMENT ;
    PORT
      LAYER M3 ;
      RECT 22.959 0.000 22.977 0.054 ;
    END
  END w0_wd_in[176]
  PIN w0_wd_in[177]
    DIRECTION OUTPUT ;
    USE SIGNAL ;
    SHAPE ABUTMENT ;
    PORT
      LAYER M3 ;
      RECT 23.247 0.000 23.265 0.054 ;
    END
  END w0_wd_in[177]
  PIN w0_wd_in[178]
    DIRECTION OUTPUT ;
    USE SIGNAL ;
    SHAPE ABUTMENT ;
    PORT
      LAYER M3 ;
      RECT 23.535 0.000 23.553 0.054 ;
    END
  END w0_wd_in[178]
  PIN w0_wd_in[179]
    DIRECTION OUTPUT ;
    USE SIGNAL ;
    SHAPE ABUTMENT ;
    PORT
      LAYER M3 ;
      RECT 23.823 0.000 23.841 0.054 ;
    END
  END w0_wd_in[179]
  PIN w0_wd_in[180]
    DIRECTION OUTPUT ;
    USE SIGNAL ;
    SHAPE ABUTMENT ;
    PORT
      LAYER M3 ;
      RECT 24.111 0.000 24.129 0.054 ;
    END
  END w0_wd_in[180]
  PIN w0_wd_in[181]
    DIRECTION OUTPUT ;
    USE SIGNAL ;
    SHAPE ABUTMENT ;
    PORT
      LAYER M3 ;
      RECT 24.399 0.000 24.417 0.054 ;
    END
  END w0_wd_in[181]
  PIN w0_wd_in[182]
    DIRECTION OUTPUT ;
    USE SIGNAL ;
    SHAPE ABUTMENT ;
    PORT
      LAYER M3 ;
      RECT 24.687 0.000 24.705 0.054 ;
    END
  END w0_wd_in[182]
  PIN w0_wd_in[183]
    DIRECTION OUTPUT ;
    USE SIGNAL ;
    SHAPE ABUTMENT ;
    PORT
      LAYER M3 ;
      RECT 24.975 0.000 24.993 0.054 ;
    END
  END w0_wd_in[183]
  PIN w0_wd_in[184]
    DIRECTION OUTPUT ;
    USE SIGNAL ;
    SHAPE ABUTMENT ;
    PORT
      LAYER M3 ;
      RECT 25.263 0.000 25.281 0.054 ;
    END
  END w0_wd_in[184]
  PIN w0_wd_in[185]
    DIRECTION OUTPUT ;
    USE SIGNAL ;
    SHAPE ABUTMENT ;
    PORT
      LAYER M3 ;
      RECT 25.551 0.000 25.569 0.054 ;
    END
  END w0_wd_in[185]
  PIN w0_wd_in[186]
    DIRECTION OUTPUT ;
    USE SIGNAL ;
    SHAPE ABUTMENT ;
    PORT
      LAYER M3 ;
      RECT 25.839 0.000 25.857 0.054 ;
    END
  END w0_wd_in[186]
  PIN w0_wd_in[187]
    DIRECTION OUTPUT ;
    USE SIGNAL ;
    SHAPE ABUTMENT ;
    PORT
      LAYER M3 ;
      RECT 26.127 0.000 26.145 0.054 ;
    END
  END w0_wd_in[187]
  PIN w0_wd_in[188]
    DIRECTION OUTPUT ;
    USE SIGNAL ;
    SHAPE ABUTMENT ;
    PORT
      LAYER M3 ;
      RECT 26.415 0.000 26.433 0.054 ;
    END
  END w0_wd_in[188]
  PIN w0_wd_in[189]
    DIRECTION OUTPUT ;
    USE SIGNAL ;
    SHAPE ABUTMENT ;
    PORT
      LAYER M3 ;
      RECT 26.703 0.000 26.721 0.054 ;
    END
  END w0_wd_in[189]
  PIN w0_wd_in[190]
    DIRECTION OUTPUT ;
    USE SIGNAL ;
    SHAPE ABUTMENT ;
    PORT
      LAYER M3 ;
      RECT 26.991 0.000 27.009 0.054 ;
    END
  END w0_wd_in[190]
  PIN w0_wd_in[191]
    DIRECTION OUTPUT ;
    USE SIGNAL ;
    SHAPE ABUTMENT ;
    PORT
      LAYER M3 ;
      RECT 27.279 0.000 27.297 0.054 ;
    END
  END w0_wd_in[191]
  PIN w0_wd_in[192]
    DIRECTION OUTPUT ;
    USE SIGNAL ;
    SHAPE ABUTMENT ;
    PORT
      LAYER M3 ;
      RECT 27.567 0.000 27.585 0.054 ;
    END
  END w0_wd_in[192]
  PIN r0_rd_out[0]
    DIRECTION OUTPUT ;
    USE SIGNAL ;
    SHAPE ABUTMENT ;
    PORT
      LAYER M3 ;
      RECT 27.855 0.000 27.873 0.054 ;
    END
  END r0_rd_out[0]
  PIN r0_rd_out[1]
    DIRECTION OUTPUT ;
    USE SIGNAL ;
    SHAPE ABUTMENT ;
    PORT
      LAYER M3 ;
      RECT 28.143 0.000 28.161 0.054 ;
    END
  END r0_rd_out[1]
  PIN r0_rd_out[2]
    DIRECTION OUTPUT ;
    USE SIGNAL ;
    SHAPE ABUTMENT ;
    PORT
      LAYER M3 ;
      RECT 28.431 0.000 28.449 0.054 ;
    END
  END r0_rd_out[2]
  PIN r0_rd_out[3]
    DIRECTION OUTPUT ;
    USE SIGNAL ;
    SHAPE ABUTMENT ;
    PORT
      LAYER M3 ;
      RECT 28.719 0.000 28.737 0.054 ;
    END
  END r0_rd_out[3]
  PIN r0_rd_out[4]
    DIRECTION OUTPUT ;
    USE SIGNAL ;
    SHAPE ABUTMENT ;
    PORT
      LAYER M3 ;
      RECT 29.007 0.000 29.025 0.054 ;
    END
  END r0_rd_out[4]
  PIN r0_rd_out[5]
    DIRECTION OUTPUT ;
    USE SIGNAL ;
    SHAPE ABUTMENT ;
    PORT
      LAYER M3 ;
      RECT 29.295 0.000 29.313 0.054 ;
    END
  END r0_rd_out[5]
  PIN r0_rd_out[6]
    DIRECTION OUTPUT ;
    USE SIGNAL ;
    SHAPE ABUTMENT ;
    PORT
      LAYER M3 ;
      RECT 29.583 0.000 29.601 0.054 ;
    END
  END r0_rd_out[6]
  PIN r0_rd_out[7]
    DIRECTION OUTPUT ;
    USE SIGNAL ;
    SHAPE ABUTMENT ;
    PORT
      LAYER M3 ;
      RECT 29.871 0.000 29.889 0.054 ;
    END
  END r0_rd_out[7]
  PIN r0_rd_out[8]
    DIRECTION OUTPUT ;
    USE SIGNAL ;
    SHAPE ABUTMENT ;
    PORT
      LAYER M3 ;
      RECT 30.159 0.000 30.177 0.054 ;
    END
  END r0_rd_out[8]
  PIN r0_rd_out[9]
    DIRECTION OUTPUT ;
    USE SIGNAL ;
    SHAPE ABUTMENT ;
    PORT
      LAYER M3 ;
      RECT 30.447 0.000 30.465 0.054 ;
    END
  END r0_rd_out[9]
  PIN r0_rd_out[10]
    DIRECTION OUTPUT ;
    USE SIGNAL ;
    SHAPE ABUTMENT ;
    PORT
      LAYER M3 ;
      RECT 30.735 0.000 30.753 0.054 ;
    END
  END r0_rd_out[10]
  PIN r0_rd_out[11]
    DIRECTION OUTPUT ;
    USE SIGNAL ;
    SHAPE ABUTMENT ;
    PORT
      LAYER M3 ;
      RECT 31.023 0.000 31.041 0.054 ;
    END
  END r0_rd_out[11]
  PIN r0_rd_out[12]
    DIRECTION OUTPUT ;
    USE SIGNAL ;
    SHAPE ABUTMENT ;
    PORT
      LAYER M3 ;
      RECT 31.311 0.000 31.329 0.054 ;
    END
  END r0_rd_out[12]
  PIN r0_rd_out[13]
    DIRECTION OUTPUT ;
    USE SIGNAL ;
    SHAPE ABUTMENT ;
    PORT
      LAYER M3 ;
      RECT 31.599 0.000 31.617 0.054 ;
    END
  END r0_rd_out[13]
  PIN r0_rd_out[14]
    DIRECTION OUTPUT ;
    USE SIGNAL ;
    SHAPE ABUTMENT ;
    PORT
      LAYER M3 ;
      RECT 31.887 0.000 31.905 0.054 ;
    END
  END r0_rd_out[14]
  PIN r0_rd_out[15]
    DIRECTION OUTPUT ;
    USE SIGNAL ;
    SHAPE ABUTMENT ;
    PORT
      LAYER M3 ;
      RECT 32.175 0.000 32.193 0.054 ;
    END
  END r0_rd_out[15]
  PIN r0_rd_out[16]
    DIRECTION OUTPUT ;
    USE SIGNAL ;
    SHAPE ABUTMENT ;
    PORT
      LAYER M3 ;
      RECT 32.463 0.000 32.481 0.054 ;
    END
  END r0_rd_out[16]
  PIN r0_rd_out[17]
    DIRECTION OUTPUT ;
    USE SIGNAL ;
    SHAPE ABUTMENT ;
    PORT
      LAYER M3 ;
      RECT 32.751 0.000 32.769 0.054 ;
    END
  END r0_rd_out[17]
  PIN r0_rd_out[18]
    DIRECTION OUTPUT ;
    USE SIGNAL ;
    SHAPE ABUTMENT ;
    PORT
      LAYER M3 ;
      RECT 33.039 0.000 33.057 0.054 ;
    END
  END r0_rd_out[18]
  PIN r0_rd_out[19]
    DIRECTION OUTPUT ;
    USE SIGNAL ;
    SHAPE ABUTMENT ;
    PORT
      LAYER M3 ;
      RECT 33.327 0.000 33.345 0.054 ;
    END
  END r0_rd_out[19]
  PIN r0_rd_out[20]
    DIRECTION OUTPUT ;
    USE SIGNAL ;
    SHAPE ABUTMENT ;
    PORT
      LAYER M3 ;
      RECT 33.615 0.000 33.633 0.054 ;
    END
  END r0_rd_out[20]
  PIN r0_rd_out[21]
    DIRECTION OUTPUT ;
    USE SIGNAL ;
    SHAPE ABUTMENT ;
    PORT
      LAYER M3 ;
      RECT 33.903 0.000 33.921 0.054 ;
    END
  END r0_rd_out[21]
  PIN r0_rd_out[22]
    DIRECTION OUTPUT ;
    USE SIGNAL ;
    SHAPE ABUTMENT ;
    PORT
      LAYER M3 ;
      RECT 34.191 0.000 34.209 0.054 ;
    END
  END r0_rd_out[22]
  PIN r0_rd_out[23]
    DIRECTION OUTPUT ;
    USE SIGNAL ;
    SHAPE ABUTMENT ;
    PORT
      LAYER M3 ;
      RECT 34.479 0.000 34.497 0.054 ;
    END
  END r0_rd_out[23]
  PIN r0_rd_out[24]
    DIRECTION OUTPUT ;
    USE SIGNAL ;
    SHAPE ABUTMENT ;
    PORT
      LAYER M3 ;
      RECT 34.767 0.000 34.785 0.054 ;
    END
  END r0_rd_out[24]
  PIN r0_rd_out[25]
    DIRECTION OUTPUT ;
    USE SIGNAL ;
    SHAPE ABUTMENT ;
    PORT
      LAYER M3 ;
      RECT 35.055 0.000 35.073 0.054 ;
    END
  END r0_rd_out[25]
  PIN r0_rd_out[26]
    DIRECTION OUTPUT ;
    USE SIGNAL ;
    SHAPE ABUTMENT ;
    PORT
      LAYER M3 ;
      RECT 35.343 0.000 35.361 0.054 ;
    END
  END r0_rd_out[26]
  PIN r0_rd_out[27]
    DIRECTION OUTPUT ;
    USE SIGNAL ;
    SHAPE ABUTMENT ;
    PORT
      LAYER M3 ;
      RECT 35.631 0.000 35.649 0.054 ;
    END
  END r0_rd_out[27]
  PIN r0_rd_out[28]
    DIRECTION OUTPUT ;
    USE SIGNAL ;
    SHAPE ABUTMENT ;
    PORT
      LAYER M3 ;
      RECT 35.919 0.000 35.937 0.054 ;
    END
  END r0_rd_out[28]
  PIN r0_rd_out[29]
    DIRECTION OUTPUT ;
    USE SIGNAL ;
    SHAPE ABUTMENT ;
    PORT
      LAYER M3 ;
      RECT 36.207 0.000 36.225 0.054 ;
    END
  END r0_rd_out[29]
  PIN r0_rd_out[30]
    DIRECTION OUTPUT ;
    USE SIGNAL ;
    SHAPE ABUTMENT ;
    PORT
      LAYER M3 ;
      RECT 36.495 0.000 36.513 0.054 ;
    END
  END r0_rd_out[30]
  PIN r0_rd_out[31]
    DIRECTION OUTPUT ;
    USE SIGNAL ;
    SHAPE ABUTMENT ;
    PORT
      LAYER M3 ;
      RECT 36.783 0.000 36.801 0.054 ;
    END
  END r0_rd_out[31]
  PIN r0_rd_out[32]
    DIRECTION OUTPUT ;
    USE SIGNAL ;
    SHAPE ABUTMENT ;
    PORT
      LAYER M3 ;
      RECT 37.071 0.000 37.089 0.054 ;
    END
  END r0_rd_out[32]
  PIN r0_rd_out[33]
    DIRECTION OUTPUT ;
    USE SIGNAL ;
    SHAPE ABUTMENT ;
    PORT
      LAYER M3 ;
      RECT 37.359 0.000 37.377 0.054 ;
    END
  END r0_rd_out[33]
  PIN r0_rd_out[34]
    DIRECTION OUTPUT ;
    USE SIGNAL ;
    SHAPE ABUTMENT ;
    PORT
      LAYER M3 ;
      RECT 37.647 0.000 37.665 0.054 ;
    END
  END r0_rd_out[34]
  PIN r0_rd_out[35]
    DIRECTION OUTPUT ;
    USE SIGNAL ;
    SHAPE ABUTMENT ;
    PORT
      LAYER M3 ;
      RECT 37.935 0.000 37.953 0.054 ;
    END
  END r0_rd_out[35]
  PIN r0_rd_out[36]
    DIRECTION OUTPUT ;
    USE SIGNAL ;
    SHAPE ABUTMENT ;
    PORT
      LAYER M3 ;
      RECT 38.223 0.000 38.241 0.054 ;
    END
  END r0_rd_out[36]
  PIN r0_rd_out[37]
    DIRECTION OUTPUT ;
    USE SIGNAL ;
    SHAPE ABUTMENT ;
    PORT
      LAYER M3 ;
      RECT 38.511 0.000 38.529 0.054 ;
    END
  END r0_rd_out[37]
  PIN r0_rd_out[38]
    DIRECTION OUTPUT ;
    USE SIGNAL ;
    SHAPE ABUTMENT ;
    PORT
      LAYER M3 ;
      RECT 38.799 0.000 38.817 0.054 ;
    END
  END r0_rd_out[38]
  PIN r0_rd_out[39]
    DIRECTION OUTPUT ;
    USE SIGNAL ;
    SHAPE ABUTMENT ;
    PORT
      LAYER M3 ;
      RECT 39.087 0.000 39.105 0.054 ;
    END
  END r0_rd_out[39]
  PIN r0_rd_out[40]
    DIRECTION OUTPUT ;
    USE SIGNAL ;
    SHAPE ABUTMENT ;
    PORT
      LAYER M3 ;
      RECT 39.375 0.000 39.393 0.054 ;
    END
  END r0_rd_out[40]
  PIN r0_rd_out[41]
    DIRECTION OUTPUT ;
    USE SIGNAL ;
    SHAPE ABUTMENT ;
    PORT
      LAYER M3 ;
      RECT 39.663 0.000 39.681 0.054 ;
    END
  END r0_rd_out[41]
  PIN r0_rd_out[42]
    DIRECTION OUTPUT ;
    USE SIGNAL ;
    SHAPE ABUTMENT ;
    PORT
      LAYER M3 ;
      RECT 39.951 0.000 39.969 0.054 ;
    END
  END r0_rd_out[42]
  PIN r0_rd_out[43]
    DIRECTION OUTPUT ;
    USE SIGNAL ;
    SHAPE ABUTMENT ;
    PORT
      LAYER M3 ;
      RECT 40.239 0.000 40.257 0.054 ;
    END
  END r0_rd_out[43]
  PIN r0_rd_out[44]
    DIRECTION OUTPUT ;
    USE SIGNAL ;
    SHAPE ABUTMENT ;
    PORT
      LAYER M3 ;
      RECT 40.527 0.000 40.545 0.054 ;
    END
  END r0_rd_out[44]
  PIN r0_rd_out[45]
    DIRECTION OUTPUT ;
    USE SIGNAL ;
    SHAPE ABUTMENT ;
    PORT
      LAYER M3 ;
      RECT 40.815 0.000 40.833 0.054 ;
    END
  END r0_rd_out[45]
  PIN r0_rd_out[46]
    DIRECTION OUTPUT ;
    USE SIGNAL ;
    SHAPE ABUTMENT ;
    PORT
      LAYER M3 ;
      RECT 41.103 0.000 41.121 0.054 ;
    END
  END r0_rd_out[46]
  PIN r0_rd_out[47]
    DIRECTION OUTPUT ;
    USE SIGNAL ;
    SHAPE ABUTMENT ;
    PORT
      LAYER M3 ;
      RECT 41.391 0.000 41.409 0.054 ;
    END
  END r0_rd_out[47]
  PIN r0_rd_out[48]
    DIRECTION OUTPUT ;
    USE SIGNAL ;
    SHAPE ABUTMENT ;
    PORT
      LAYER M3 ;
      RECT 41.679 0.000 41.697 0.054 ;
    END
  END r0_rd_out[48]
  PIN r0_rd_out[49]
    DIRECTION OUTPUT ;
    USE SIGNAL ;
    SHAPE ABUTMENT ;
    PORT
      LAYER M3 ;
      RECT 41.967 0.000 41.985 0.054 ;
    END
  END r0_rd_out[49]
  PIN r0_rd_out[50]
    DIRECTION OUTPUT ;
    USE SIGNAL ;
    SHAPE ABUTMENT ;
    PORT
      LAYER M3 ;
      RECT 42.255 0.000 42.273 0.054 ;
    END
  END r0_rd_out[50]
  PIN r0_rd_out[51]
    DIRECTION OUTPUT ;
    USE SIGNAL ;
    SHAPE ABUTMENT ;
    PORT
      LAYER M3 ;
      RECT 42.543 0.000 42.561 0.054 ;
    END
  END r0_rd_out[51]
  PIN r0_rd_out[52]
    DIRECTION OUTPUT ;
    USE SIGNAL ;
    SHAPE ABUTMENT ;
    PORT
      LAYER M3 ;
      RECT 42.831 0.000 42.849 0.054 ;
    END
  END r0_rd_out[52]
  PIN r0_rd_out[53]
    DIRECTION OUTPUT ;
    USE SIGNAL ;
    SHAPE ABUTMENT ;
    PORT
      LAYER M3 ;
      RECT 43.119 0.000 43.137 0.054 ;
    END
  END r0_rd_out[53]
  PIN r0_rd_out[54]
    DIRECTION OUTPUT ;
    USE SIGNAL ;
    SHAPE ABUTMENT ;
    PORT
      LAYER M3 ;
      RECT 43.407 0.000 43.425 0.054 ;
    END
  END r0_rd_out[54]
  PIN r0_rd_out[55]
    DIRECTION OUTPUT ;
    USE SIGNAL ;
    SHAPE ABUTMENT ;
    PORT
      LAYER M3 ;
      RECT 43.695 0.000 43.713 0.054 ;
    END
  END r0_rd_out[55]
  PIN r0_rd_out[56]
    DIRECTION OUTPUT ;
    USE SIGNAL ;
    SHAPE ABUTMENT ;
    PORT
      LAYER M3 ;
      RECT 43.983 0.000 44.001 0.054 ;
    END
  END r0_rd_out[56]
  PIN r0_rd_out[57]
    DIRECTION OUTPUT ;
    USE SIGNAL ;
    SHAPE ABUTMENT ;
    PORT
      LAYER M3 ;
      RECT 44.271 0.000 44.289 0.054 ;
    END
  END r0_rd_out[57]
  PIN r0_rd_out[58]
    DIRECTION OUTPUT ;
    USE SIGNAL ;
    SHAPE ABUTMENT ;
    PORT
      LAYER M3 ;
      RECT 44.559 0.000 44.577 0.054 ;
    END
  END r0_rd_out[58]
  PIN r0_rd_out[59]
    DIRECTION OUTPUT ;
    USE SIGNAL ;
    SHAPE ABUTMENT ;
    PORT
      LAYER M3 ;
      RECT 44.847 0.000 44.865 0.054 ;
    END
  END r0_rd_out[59]
  PIN r0_rd_out[60]
    DIRECTION OUTPUT ;
    USE SIGNAL ;
    SHAPE ABUTMENT ;
    PORT
      LAYER M3 ;
      RECT 45.135 0.000 45.153 0.054 ;
    END
  END r0_rd_out[60]
  PIN r0_rd_out[61]
    DIRECTION OUTPUT ;
    USE SIGNAL ;
    SHAPE ABUTMENT ;
    PORT
      LAYER M3 ;
      RECT 45.423 0.000 45.441 0.054 ;
    END
  END r0_rd_out[61]
  PIN r0_rd_out[62]
    DIRECTION OUTPUT ;
    USE SIGNAL ;
    SHAPE ABUTMENT ;
    PORT
      LAYER M3 ;
      RECT 45.711 0.000 45.729 0.054 ;
    END
  END r0_rd_out[62]
  PIN r0_rd_out[63]
    DIRECTION OUTPUT ;
    USE SIGNAL ;
    SHAPE ABUTMENT ;
    PORT
      LAYER M3 ;
      RECT 45.999 0.000 46.017 0.054 ;
    END
  END r0_rd_out[63]
  PIN r0_rd_out[64]
    DIRECTION OUTPUT ;
    USE SIGNAL ;
    SHAPE ABUTMENT ;
    PORT
      LAYER M3 ;
      RECT 46.287 0.000 46.305 0.054 ;
    END
  END r0_rd_out[64]
  PIN r0_rd_out[65]
    DIRECTION OUTPUT ;
    USE SIGNAL ;
    SHAPE ABUTMENT ;
    PORT
      LAYER M3 ;
      RECT 46.575 0.000 46.593 0.054 ;
    END
  END r0_rd_out[65]
  PIN r0_rd_out[66]
    DIRECTION OUTPUT ;
    USE SIGNAL ;
    SHAPE ABUTMENT ;
    PORT
      LAYER M3 ;
      RECT 46.863 0.000 46.881 0.054 ;
    END
  END r0_rd_out[66]
  PIN r0_rd_out[67]
    DIRECTION OUTPUT ;
    USE SIGNAL ;
    SHAPE ABUTMENT ;
    PORT
      LAYER M3 ;
      RECT 47.151 0.000 47.169 0.054 ;
    END
  END r0_rd_out[67]
  PIN r0_rd_out[68]
    DIRECTION OUTPUT ;
    USE SIGNAL ;
    SHAPE ABUTMENT ;
    PORT
      LAYER M3 ;
      RECT 47.439 0.000 47.457 0.054 ;
    END
  END r0_rd_out[68]
  PIN r0_rd_out[69]
    DIRECTION OUTPUT ;
    USE SIGNAL ;
    SHAPE ABUTMENT ;
    PORT
      LAYER M3 ;
      RECT 47.727 0.000 47.745 0.054 ;
    END
  END r0_rd_out[69]
  PIN r0_rd_out[70]
    DIRECTION OUTPUT ;
    USE SIGNAL ;
    SHAPE ABUTMENT ;
    PORT
      LAYER M3 ;
      RECT 48.015 0.000 48.033 0.054 ;
    END
  END r0_rd_out[70]
  PIN r0_rd_out[71]
    DIRECTION OUTPUT ;
    USE SIGNAL ;
    SHAPE ABUTMENT ;
    PORT
      LAYER M3 ;
      RECT 48.303 0.000 48.321 0.054 ;
    END
  END r0_rd_out[71]
  PIN r0_rd_out[72]
    DIRECTION OUTPUT ;
    USE SIGNAL ;
    SHAPE ABUTMENT ;
    PORT
      LAYER M3 ;
      RECT 48.591 0.000 48.609 0.054 ;
    END
  END r0_rd_out[72]
  PIN r0_rd_out[73]
    DIRECTION OUTPUT ;
    USE SIGNAL ;
    SHAPE ABUTMENT ;
    PORT
      LAYER M3 ;
      RECT 48.879 0.000 48.897 0.054 ;
    END
  END r0_rd_out[73]
  PIN r0_rd_out[74]
    DIRECTION OUTPUT ;
    USE SIGNAL ;
    SHAPE ABUTMENT ;
    PORT
      LAYER M3 ;
      RECT 49.167 0.000 49.185 0.054 ;
    END
  END r0_rd_out[74]
  PIN r0_rd_out[75]
    DIRECTION OUTPUT ;
    USE SIGNAL ;
    SHAPE ABUTMENT ;
    PORT
      LAYER M3 ;
      RECT 49.455 0.000 49.473 0.054 ;
    END
  END r0_rd_out[75]
  PIN r0_rd_out[76]
    DIRECTION OUTPUT ;
    USE SIGNAL ;
    SHAPE ABUTMENT ;
    PORT
      LAYER M3 ;
      RECT 49.743 0.000 49.761 0.054 ;
    END
  END r0_rd_out[76]
  PIN r0_rd_out[77]
    DIRECTION OUTPUT ;
    USE SIGNAL ;
    SHAPE ABUTMENT ;
    PORT
      LAYER M3 ;
      RECT 50.031 0.000 50.049 0.054 ;
    END
  END r0_rd_out[77]
  PIN r0_rd_out[78]
    DIRECTION OUTPUT ;
    USE SIGNAL ;
    SHAPE ABUTMENT ;
    PORT
      LAYER M3 ;
      RECT 50.319 0.000 50.337 0.054 ;
    END
  END r0_rd_out[78]
  PIN r0_rd_out[79]
    DIRECTION OUTPUT ;
    USE SIGNAL ;
    SHAPE ABUTMENT ;
    PORT
      LAYER M3 ;
      RECT 50.607 0.000 50.625 0.054 ;
    END
  END r0_rd_out[79]
  PIN r0_rd_out[80]
    DIRECTION OUTPUT ;
    USE SIGNAL ;
    SHAPE ABUTMENT ;
    PORT
      LAYER M3 ;
      RECT 50.895 0.000 50.913 0.054 ;
    END
  END r0_rd_out[80]
  PIN r0_rd_out[81]
    DIRECTION OUTPUT ;
    USE SIGNAL ;
    SHAPE ABUTMENT ;
    PORT
      LAYER M3 ;
      RECT 51.183 0.000 51.201 0.054 ;
    END
  END r0_rd_out[81]
  PIN r0_rd_out[82]
    DIRECTION OUTPUT ;
    USE SIGNAL ;
    SHAPE ABUTMENT ;
    PORT
      LAYER M3 ;
      RECT 51.471 0.000 51.489 0.054 ;
    END
  END r0_rd_out[82]
  PIN r0_rd_out[83]
    DIRECTION OUTPUT ;
    USE SIGNAL ;
    SHAPE ABUTMENT ;
    PORT
      LAYER M3 ;
      RECT 51.759 0.000 51.777 0.054 ;
    END
  END r0_rd_out[83]
  PIN r0_rd_out[84]
    DIRECTION OUTPUT ;
    USE SIGNAL ;
    SHAPE ABUTMENT ;
    PORT
      LAYER M3 ;
      RECT 52.047 0.000 52.065 0.054 ;
    END
  END r0_rd_out[84]
  PIN r0_rd_out[85]
    DIRECTION OUTPUT ;
    USE SIGNAL ;
    SHAPE ABUTMENT ;
    PORT
      LAYER M3 ;
      RECT 52.335 0.000 52.353 0.054 ;
    END
  END r0_rd_out[85]
  PIN r0_rd_out[86]
    DIRECTION OUTPUT ;
    USE SIGNAL ;
    SHAPE ABUTMENT ;
    PORT
      LAYER M3 ;
      RECT 52.623 0.000 52.641 0.054 ;
    END
  END r0_rd_out[86]
  PIN r0_rd_out[87]
    DIRECTION OUTPUT ;
    USE SIGNAL ;
    SHAPE ABUTMENT ;
    PORT
      LAYER M3 ;
      RECT 52.911 0.000 52.929 0.054 ;
    END
  END r0_rd_out[87]
  PIN r0_rd_out[88]
    DIRECTION OUTPUT ;
    USE SIGNAL ;
    SHAPE ABUTMENT ;
    PORT
      LAYER M3 ;
      RECT 53.199 0.000 53.217 0.054 ;
    END
  END r0_rd_out[88]
  PIN r0_rd_out[89]
    DIRECTION OUTPUT ;
    USE SIGNAL ;
    SHAPE ABUTMENT ;
    PORT
      LAYER M3 ;
      RECT 53.487 0.000 53.505 0.054 ;
    END
  END r0_rd_out[89]
  PIN r0_rd_out[90]
    DIRECTION OUTPUT ;
    USE SIGNAL ;
    SHAPE ABUTMENT ;
    PORT
      LAYER M3 ;
      RECT 53.775 0.000 53.793 0.054 ;
    END
  END r0_rd_out[90]
  PIN r0_rd_out[91]
    DIRECTION OUTPUT ;
    USE SIGNAL ;
    SHAPE ABUTMENT ;
    PORT
      LAYER M3 ;
      RECT 54.063 0.000 54.081 0.054 ;
    END
  END r0_rd_out[91]
  PIN r0_rd_out[92]
    DIRECTION OUTPUT ;
    USE SIGNAL ;
    SHAPE ABUTMENT ;
    PORT
      LAYER M3 ;
      RECT 54.351 0.000 54.369 0.054 ;
    END
  END r0_rd_out[92]
  PIN r0_rd_out[93]
    DIRECTION OUTPUT ;
    USE SIGNAL ;
    SHAPE ABUTMENT ;
    PORT
      LAYER M3 ;
      RECT 54.639 0.000 54.657 0.054 ;
    END
  END r0_rd_out[93]
  PIN r0_rd_out[94]
    DIRECTION OUTPUT ;
    USE SIGNAL ;
    SHAPE ABUTMENT ;
    PORT
      LAYER M3 ;
      RECT 54.927 0.000 54.945 0.054 ;
    END
  END r0_rd_out[94]
  PIN r0_rd_out[95]
    DIRECTION OUTPUT ;
    USE SIGNAL ;
    SHAPE ABUTMENT ;
    PORT
      LAYER M3 ;
      RECT 55.215 0.000 55.233 0.054 ;
    END
  END r0_rd_out[95]
  PIN r0_rd_out[96]
    DIRECTION OUTPUT ;
    USE SIGNAL ;
    SHAPE ABUTMENT ;
    PORT
      LAYER M3 ;
      RECT 55.503 0.000 55.521 0.054 ;
    END
  END r0_rd_out[96]
  PIN r0_rd_out[97]
    DIRECTION OUTPUT ;
    USE SIGNAL ;
    SHAPE ABUTMENT ;
    PORT
      LAYER M3 ;
      RECT 27.855 19.873 27.873 19.927 ;
    END
  END r0_rd_out[97]
  PIN r0_rd_out[98]
    DIRECTION OUTPUT ;
    USE SIGNAL ;
    SHAPE ABUTMENT ;
    PORT
      LAYER M3 ;
      RECT 28.143 19.873 28.161 19.927 ;
    END
  END r0_rd_out[98]
  PIN r0_rd_out[99]
    DIRECTION OUTPUT ;
    USE SIGNAL ;
    SHAPE ABUTMENT ;
    PORT
      LAYER M3 ;
      RECT 28.431 19.873 28.449 19.927 ;
    END
  END r0_rd_out[99]
  PIN r0_rd_out[100]
    DIRECTION OUTPUT ;
    USE SIGNAL ;
    SHAPE ABUTMENT ;
    PORT
      LAYER M3 ;
      RECT 28.719 19.873 28.737 19.927 ;
    END
  END r0_rd_out[100]
  PIN r0_rd_out[101]
    DIRECTION OUTPUT ;
    USE SIGNAL ;
    SHAPE ABUTMENT ;
    PORT
      LAYER M3 ;
      RECT 29.007 19.873 29.025 19.927 ;
    END
  END r0_rd_out[101]
  PIN r0_rd_out[102]
    DIRECTION OUTPUT ;
    USE SIGNAL ;
    SHAPE ABUTMENT ;
    PORT
      LAYER M3 ;
      RECT 29.295 19.873 29.313 19.927 ;
    END
  END r0_rd_out[102]
  PIN r0_rd_out[103]
    DIRECTION OUTPUT ;
    USE SIGNAL ;
    SHAPE ABUTMENT ;
    PORT
      LAYER M3 ;
      RECT 29.583 19.873 29.601 19.927 ;
    END
  END r0_rd_out[103]
  PIN r0_rd_out[104]
    DIRECTION OUTPUT ;
    USE SIGNAL ;
    SHAPE ABUTMENT ;
    PORT
      LAYER M3 ;
      RECT 29.871 19.873 29.889 19.927 ;
    END
  END r0_rd_out[104]
  PIN r0_rd_out[105]
    DIRECTION OUTPUT ;
    USE SIGNAL ;
    SHAPE ABUTMENT ;
    PORT
      LAYER M3 ;
      RECT 30.159 19.873 30.177 19.927 ;
    END
  END r0_rd_out[105]
  PIN r0_rd_out[106]
    DIRECTION OUTPUT ;
    USE SIGNAL ;
    SHAPE ABUTMENT ;
    PORT
      LAYER M3 ;
      RECT 30.447 19.873 30.465 19.927 ;
    END
  END r0_rd_out[106]
  PIN r0_rd_out[107]
    DIRECTION OUTPUT ;
    USE SIGNAL ;
    SHAPE ABUTMENT ;
    PORT
      LAYER M3 ;
      RECT 30.735 19.873 30.753 19.927 ;
    END
  END r0_rd_out[107]
  PIN r0_rd_out[108]
    DIRECTION OUTPUT ;
    USE SIGNAL ;
    SHAPE ABUTMENT ;
    PORT
      LAYER M3 ;
      RECT 31.023 19.873 31.041 19.927 ;
    END
  END r0_rd_out[108]
  PIN r0_rd_out[109]
    DIRECTION OUTPUT ;
    USE SIGNAL ;
    SHAPE ABUTMENT ;
    PORT
      LAYER M3 ;
      RECT 31.311 19.873 31.329 19.927 ;
    END
  END r0_rd_out[109]
  PIN r0_rd_out[110]
    DIRECTION OUTPUT ;
    USE SIGNAL ;
    SHAPE ABUTMENT ;
    PORT
      LAYER M3 ;
      RECT 31.599 19.873 31.617 19.927 ;
    END
  END r0_rd_out[110]
  PIN r0_rd_out[111]
    DIRECTION OUTPUT ;
    USE SIGNAL ;
    SHAPE ABUTMENT ;
    PORT
      LAYER M3 ;
      RECT 31.887 19.873 31.905 19.927 ;
    END
  END r0_rd_out[111]
  PIN r0_rd_out[112]
    DIRECTION OUTPUT ;
    USE SIGNAL ;
    SHAPE ABUTMENT ;
    PORT
      LAYER M3 ;
      RECT 32.175 19.873 32.193 19.927 ;
    END
  END r0_rd_out[112]
  PIN r0_rd_out[113]
    DIRECTION OUTPUT ;
    USE SIGNAL ;
    SHAPE ABUTMENT ;
    PORT
      LAYER M3 ;
      RECT 32.463 19.873 32.481 19.927 ;
    END
  END r0_rd_out[113]
  PIN r0_rd_out[114]
    DIRECTION OUTPUT ;
    USE SIGNAL ;
    SHAPE ABUTMENT ;
    PORT
      LAYER M3 ;
      RECT 32.751 19.873 32.769 19.927 ;
    END
  END r0_rd_out[114]
  PIN r0_rd_out[115]
    DIRECTION OUTPUT ;
    USE SIGNAL ;
    SHAPE ABUTMENT ;
    PORT
      LAYER M3 ;
      RECT 33.039 19.873 33.057 19.927 ;
    END
  END r0_rd_out[115]
  PIN r0_rd_out[116]
    DIRECTION OUTPUT ;
    USE SIGNAL ;
    SHAPE ABUTMENT ;
    PORT
      LAYER M3 ;
      RECT 33.327 19.873 33.345 19.927 ;
    END
  END r0_rd_out[116]
  PIN r0_rd_out[117]
    DIRECTION OUTPUT ;
    USE SIGNAL ;
    SHAPE ABUTMENT ;
    PORT
      LAYER M3 ;
      RECT 33.615 19.873 33.633 19.927 ;
    END
  END r0_rd_out[117]
  PIN r0_rd_out[118]
    DIRECTION OUTPUT ;
    USE SIGNAL ;
    SHAPE ABUTMENT ;
    PORT
      LAYER M3 ;
      RECT 33.903 19.873 33.921 19.927 ;
    END
  END r0_rd_out[118]
  PIN r0_rd_out[119]
    DIRECTION OUTPUT ;
    USE SIGNAL ;
    SHAPE ABUTMENT ;
    PORT
      LAYER M3 ;
      RECT 34.191 19.873 34.209 19.927 ;
    END
  END r0_rd_out[119]
  PIN r0_rd_out[120]
    DIRECTION OUTPUT ;
    USE SIGNAL ;
    SHAPE ABUTMENT ;
    PORT
      LAYER M3 ;
      RECT 34.479 19.873 34.497 19.927 ;
    END
  END r0_rd_out[120]
  PIN r0_rd_out[121]
    DIRECTION OUTPUT ;
    USE SIGNAL ;
    SHAPE ABUTMENT ;
    PORT
      LAYER M3 ;
      RECT 34.767 19.873 34.785 19.927 ;
    END
  END r0_rd_out[121]
  PIN r0_rd_out[122]
    DIRECTION OUTPUT ;
    USE SIGNAL ;
    SHAPE ABUTMENT ;
    PORT
      LAYER M3 ;
      RECT 35.055 19.873 35.073 19.927 ;
    END
  END r0_rd_out[122]
  PIN r0_rd_out[123]
    DIRECTION OUTPUT ;
    USE SIGNAL ;
    SHAPE ABUTMENT ;
    PORT
      LAYER M3 ;
      RECT 35.343 19.873 35.361 19.927 ;
    END
  END r0_rd_out[123]
  PIN r0_rd_out[124]
    DIRECTION OUTPUT ;
    USE SIGNAL ;
    SHAPE ABUTMENT ;
    PORT
      LAYER M3 ;
      RECT 35.631 19.873 35.649 19.927 ;
    END
  END r0_rd_out[124]
  PIN r0_rd_out[125]
    DIRECTION OUTPUT ;
    USE SIGNAL ;
    SHAPE ABUTMENT ;
    PORT
      LAYER M3 ;
      RECT 35.919 19.873 35.937 19.927 ;
    END
  END r0_rd_out[125]
  PIN r0_rd_out[126]
    DIRECTION OUTPUT ;
    USE SIGNAL ;
    SHAPE ABUTMENT ;
    PORT
      LAYER M3 ;
      RECT 36.207 19.873 36.225 19.927 ;
    END
  END r0_rd_out[126]
  PIN r0_rd_out[127]
    DIRECTION OUTPUT ;
    USE SIGNAL ;
    SHAPE ABUTMENT ;
    PORT
      LAYER M3 ;
      RECT 36.495 19.873 36.513 19.927 ;
    END
  END r0_rd_out[127]
  PIN r0_rd_out[128]
    DIRECTION OUTPUT ;
    USE SIGNAL ;
    SHAPE ABUTMENT ;
    PORT
      LAYER M3 ;
      RECT 36.783 19.873 36.801 19.927 ;
    END
  END r0_rd_out[128]
  PIN r0_rd_out[129]
    DIRECTION OUTPUT ;
    USE SIGNAL ;
    SHAPE ABUTMENT ;
    PORT
      LAYER M3 ;
      RECT 37.071 19.873 37.089 19.927 ;
    END
  END r0_rd_out[129]
  PIN r0_rd_out[130]
    DIRECTION OUTPUT ;
    USE SIGNAL ;
    SHAPE ABUTMENT ;
    PORT
      LAYER M3 ;
      RECT 37.359 19.873 37.377 19.927 ;
    END
  END r0_rd_out[130]
  PIN r0_rd_out[131]
    DIRECTION OUTPUT ;
    USE SIGNAL ;
    SHAPE ABUTMENT ;
    PORT
      LAYER M3 ;
      RECT 37.647 19.873 37.665 19.927 ;
    END
  END r0_rd_out[131]
  PIN r0_rd_out[132]
    DIRECTION OUTPUT ;
    USE SIGNAL ;
    SHAPE ABUTMENT ;
    PORT
      LAYER M3 ;
      RECT 37.935 19.873 37.953 19.927 ;
    END
  END r0_rd_out[132]
  PIN r0_rd_out[133]
    DIRECTION OUTPUT ;
    USE SIGNAL ;
    SHAPE ABUTMENT ;
    PORT
      LAYER M3 ;
      RECT 38.223 19.873 38.241 19.927 ;
    END
  END r0_rd_out[133]
  PIN r0_rd_out[134]
    DIRECTION OUTPUT ;
    USE SIGNAL ;
    SHAPE ABUTMENT ;
    PORT
      LAYER M3 ;
      RECT 38.511 19.873 38.529 19.927 ;
    END
  END r0_rd_out[134]
  PIN r0_rd_out[135]
    DIRECTION OUTPUT ;
    USE SIGNAL ;
    SHAPE ABUTMENT ;
    PORT
      LAYER M3 ;
      RECT 38.799 19.873 38.817 19.927 ;
    END
  END r0_rd_out[135]
  PIN r0_rd_out[136]
    DIRECTION OUTPUT ;
    USE SIGNAL ;
    SHAPE ABUTMENT ;
    PORT
      LAYER M3 ;
      RECT 39.087 19.873 39.105 19.927 ;
    END
  END r0_rd_out[136]
  PIN r0_rd_out[137]
    DIRECTION OUTPUT ;
    USE SIGNAL ;
    SHAPE ABUTMENT ;
    PORT
      LAYER M3 ;
      RECT 39.375 19.873 39.393 19.927 ;
    END
  END r0_rd_out[137]
  PIN r0_rd_out[138]
    DIRECTION OUTPUT ;
    USE SIGNAL ;
    SHAPE ABUTMENT ;
    PORT
      LAYER M3 ;
      RECT 39.663 19.873 39.681 19.927 ;
    END
  END r0_rd_out[138]
  PIN r0_rd_out[139]
    DIRECTION OUTPUT ;
    USE SIGNAL ;
    SHAPE ABUTMENT ;
    PORT
      LAYER M3 ;
      RECT 39.951 19.873 39.969 19.927 ;
    END
  END r0_rd_out[139]
  PIN r0_rd_out[140]
    DIRECTION OUTPUT ;
    USE SIGNAL ;
    SHAPE ABUTMENT ;
    PORT
      LAYER M3 ;
      RECT 40.239 19.873 40.257 19.927 ;
    END
  END r0_rd_out[140]
  PIN r0_rd_out[141]
    DIRECTION OUTPUT ;
    USE SIGNAL ;
    SHAPE ABUTMENT ;
    PORT
      LAYER M3 ;
      RECT 40.527 19.873 40.545 19.927 ;
    END
  END r0_rd_out[141]
  PIN r0_rd_out[142]
    DIRECTION OUTPUT ;
    USE SIGNAL ;
    SHAPE ABUTMENT ;
    PORT
      LAYER M3 ;
      RECT 40.815 19.873 40.833 19.927 ;
    END
  END r0_rd_out[142]
  PIN r0_rd_out[143]
    DIRECTION OUTPUT ;
    USE SIGNAL ;
    SHAPE ABUTMENT ;
    PORT
      LAYER M3 ;
      RECT 41.103 19.873 41.121 19.927 ;
    END
  END r0_rd_out[143]
  PIN r0_rd_out[144]
    DIRECTION OUTPUT ;
    USE SIGNAL ;
    SHAPE ABUTMENT ;
    PORT
      LAYER M3 ;
      RECT 41.391 19.873 41.409 19.927 ;
    END
  END r0_rd_out[144]
  PIN r0_rd_out[145]
    DIRECTION OUTPUT ;
    USE SIGNAL ;
    SHAPE ABUTMENT ;
    PORT
      LAYER M3 ;
      RECT 41.679 19.873 41.697 19.927 ;
    END
  END r0_rd_out[145]
  PIN r0_rd_out[146]
    DIRECTION OUTPUT ;
    USE SIGNAL ;
    SHAPE ABUTMENT ;
    PORT
      LAYER M3 ;
      RECT 41.967 19.873 41.985 19.927 ;
    END
  END r0_rd_out[146]
  PIN r0_rd_out[147]
    DIRECTION OUTPUT ;
    USE SIGNAL ;
    SHAPE ABUTMENT ;
    PORT
      LAYER M3 ;
      RECT 42.255 19.873 42.273 19.927 ;
    END
  END r0_rd_out[147]
  PIN r0_rd_out[148]
    DIRECTION OUTPUT ;
    USE SIGNAL ;
    SHAPE ABUTMENT ;
    PORT
      LAYER M3 ;
      RECT 42.543 19.873 42.561 19.927 ;
    END
  END r0_rd_out[148]
  PIN r0_rd_out[149]
    DIRECTION OUTPUT ;
    USE SIGNAL ;
    SHAPE ABUTMENT ;
    PORT
      LAYER M3 ;
      RECT 42.831 19.873 42.849 19.927 ;
    END
  END r0_rd_out[149]
  PIN r0_rd_out[150]
    DIRECTION OUTPUT ;
    USE SIGNAL ;
    SHAPE ABUTMENT ;
    PORT
      LAYER M3 ;
      RECT 43.119 19.873 43.137 19.927 ;
    END
  END r0_rd_out[150]
  PIN r0_rd_out[151]
    DIRECTION OUTPUT ;
    USE SIGNAL ;
    SHAPE ABUTMENT ;
    PORT
      LAYER M3 ;
      RECT 43.407 19.873 43.425 19.927 ;
    END
  END r0_rd_out[151]
  PIN r0_rd_out[152]
    DIRECTION OUTPUT ;
    USE SIGNAL ;
    SHAPE ABUTMENT ;
    PORT
      LAYER M3 ;
      RECT 43.695 19.873 43.713 19.927 ;
    END
  END r0_rd_out[152]
  PIN r0_rd_out[153]
    DIRECTION OUTPUT ;
    USE SIGNAL ;
    SHAPE ABUTMENT ;
    PORT
      LAYER M3 ;
      RECT 43.983 19.873 44.001 19.927 ;
    END
  END r0_rd_out[153]
  PIN r0_rd_out[154]
    DIRECTION OUTPUT ;
    USE SIGNAL ;
    SHAPE ABUTMENT ;
    PORT
      LAYER M3 ;
      RECT 44.271 19.873 44.289 19.927 ;
    END
  END r0_rd_out[154]
  PIN r0_rd_out[155]
    DIRECTION OUTPUT ;
    USE SIGNAL ;
    SHAPE ABUTMENT ;
    PORT
      LAYER M3 ;
      RECT 44.559 19.873 44.577 19.927 ;
    END
  END r0_rd_out[155]
  PIN r0_rd_out[156]
    DIRECTION OUTPUT ;
    USE SIGNAL ;
    SHAPE ABUTMENT ;
    PORT
      LAYER M3 ;
      RECT 44.847 19.873 44.865 19.927 ;
    END
  END r0_rd_out[156]
  PIN r0_rd_out[157]
    DIRECTION OUTPUT ;
    USE SIGNAL ;
    SHAPE ABUTMENT ;
    PORT
      LAYER M3 ;
      RECT 45.135 19.873 45.153 19.927 ;
    END
  END r0_rd_out[157]
  PIN r0_rd_out[158]
    DIRECTION OUTPUT ;
    USE SIGNAL ;
    SHAPE ABUTMENT ;
    PORT
      LAYER M3 ;
      RECT 45.423 19.873 45.441 19.927 ;
    END
  END r0_rd_out[158]
  PIN r0_rd_out[159]
    DIRECTION OUTPUT ;
    USE SIGNAL ;
    SHAPE ABUTMENT ;
    PORT
      LAYER M3 ;
      RECT 45.711 19.873 45.729 19.927 ;
    END
  END r0_rd_out[159]
  PIN r0_rd_out[160]
    DIRECTION OUTPUT ;
    USE SIGNAL ;
    SHAPE ABUTMENT ;
    PORT
      LAYER M3 ;
      RECT 45.999 19.873 46.017 19.927 ;
    END
  END r0_rd_out[160]
  PIN r0_rd_out[161]
    DIRECTION OUTPUT ;
    USE SIGNAL ;
    SHAPE ABUTMENT ;
    PORT
      LAYER M3 ;
      RECT 46.287 19.873 46.305 19.927 ;
    END
  END r0_rd_out[161]
  PIN r0_rd_out[162]
    DIRECTION OUTPUT ;
    USE SIGNAL ;
    SHAPE ABUTMENT ;
    PORT
      LAYER M3 ;
      RECT 46.575 19.873 46.593 19.927 ;
    END
  END r0_rd_out[162]
  PIN r0_rd_out[163]
    DIRECTION OUTPUT ;
    USE SIGNAL ;
    SHAPE ABUTMENT ;
    PORT
      LAYER M3 ;
      RECT 46.863 19.873 46.881 19.927 ;
    END
  END r0_rd_out[163]
  PIN r0_rd_out[164]
    DIRECTION OUTPUT ;
    USE SIGNAL ;
    SHAPE ABUTMENT ;
    PORT
      LAYER M3 ;
      RECT 47.151 19.873 47.169 19.927 ;
    END
  END r0_rd_out[164]
  PIN r0_rd_out[165]
    DIRECTION OUTPUT ;
    USE SIGNAL ;
    SHAPE ABUTMENT ;
    PORT
      LAYER M3 ;
      RECT 47.439 19.873 47.457 19.927 ;
    END
  END r0_rd_out[165]
  PIN r0_rd_out[166]
    DIRECTION OUTPUT ;
    USE SIGNAL ;
    SHAPE ABUTMENT ;
    PORT
      LAYER M3 ;
      RECT 47.727 19.873 47.745 19.927 ;
    END
  END r0_rd_out[166]
  PIN r0_rd_out[167]
    DIRECTION OUTPUT ;
    USE SIGNAL ;
    SHAPE ABUTMENT ;
    PORT
      LAYER M3 ;
      RECT 48.015 19.873 48.033 19.927 ;
    END
  END r0_rd_out[167]
  PIN r0_rd_out[168]
    DIRECTION OUTPUT ;
    USE SIGNAL ;
    SHAPE ABUTMENT ;
    PORT
      LAYER M3 ;
      RECT 48.303 19.873 48.321 19.927 ;
    END
  END r0_rd_out[168]
  PIN r0_rd_out[169]
    DIRECTION OUTPUT ;
    USE SIGNAL ;
    SHAPE ABUTMENT ;
    PORT
      LAYER M3 ;
      RECT 48.591 19.873 48.609 19.927 ;
    END
  END r0_rd_out[169]
  PIN r0_rd_out[170]
    DIRECTION OUTPUT ;
    USE SIGNAL ;
    SHAPE ABUTMENT ;
    PORT
      LAYER M3 ;
      RECT 48.879 19.873 48.897 19.927 ;
    END
  END r0_rd_out[170]
  PIN r0_rd_out[171]
    DIRECTION OUTPUT ;
    USE SIGNAL ;
    SHAPE ABUTMENT ;
    PORT
      LAYER M3 ;
      RECT 49.167 19.873 49.185 19.927 ;
    END
  END r0_rd_out[171]
  PIN r0_rd_out[172]
    DIRECTION OUTPUT ;
    USE SIGNAL ;
    SHAPE ABUTMENT ;
    PORT
      LAYER M3 ;
      RECT 49.455 19.873 49.473 19.927 ;
    END
  END r0_rd_out[172]
  PIN r0_rd_out[173]
    DIRECTION OUTPUT ;
    USE SIGNAL ;
    SHAPE ABUTMENT ;
    PORT
      LAYER M3 ;
      RECT 49.743 19.873 49.761 19.927 ;
    END
  END r0_rd_out[173]
  PIN r0_rd_out[174]
    DIRECTION OUTPUT ;
    USE SIGNAL ;
    SHAPE ABUTMENT ;
    PORT
      LAYER M3 ;
      RECT 50.031 19.873 50.049 19.927 ;
    END
  END r0_rd_out[174]
  PIN r0_rd_out[175]
    DIRECTION OUTPUT ;
    USE SIGNAL ;
    SHAPE ABUTMENT ;
    PORT
      LAYER M3 ;
      RECT 50.319 19.873 50.337 19.927 ;
    END
  END r0_rd_out[175]
  PIN r0_rd_out[176]
    DIRECTION OUTPUT ;
    USE SIGNAL ;
    SHAPE ABUTMENT ;
    PORT
      LAYER M3 ;
      RECT 50.607 19.873 50.625 19.927 ;
    END
  END r0_rd_out[176]
  PIN r0_rd_out[177]
    DIRECTION OUTPUT ;
    USE SIGNAL ;
    SHAPE ABUTMENT ;
    PORT
      LAYER M3 ;
      RECT 50.895 19.873 50.913 19.927 ;
    END
  END r0_rd_out[177]
  PIN r0_rd_out[178]
    DIRECTION OUTPUT ;
    USE SIGNAL ;
    SHAPE ABUTMENT ;
    PORT
      LAYER M3 ;
      RECT 51.183 19.873 51.201 19.927 ;
    END
  END r0_rd_out[178]
  PIN r0_rd_out[179]
    DIRECTION OUTPUT ;
    USE SIGNAL ;
    SHAPE ABUTMENT ;
    PORT
      LAYER M3 ;
      RECT 51.471 19.873 51.489 19.927 ;
    END
  END r0_rd_out[179]
  PIN r0_rd_out[180]
    DIRECTION OUTPUT ;
    USE SIGNAL ;
    SHAPE ABUTMENT ;
    PORT
      LAYER M3 ;
      RECT 51.759 19.873 51.777 19.927 ;
    END
  END r0_rd_out[180]
  PIN r0_rd_out[181]
    DIRECTION OUTPUT ;
    USE SIGNAL ;
    SHAPE ABUTMENT ;
    PORT
      LAYER M3 ;
      RECT 52.047 19.873 52.065 19.927 ;
    END
  END r0_rd_out[181]
  PIN r0_rd_out[182]
    DIRECTION OUTPUT ;
    USE SIGNAL ;
    SHAPE ABUTMENT ;
    PORT
      LAYER M3 ;
      RECT 52.335 19.873 52.353 19.927 ;
    END
  END r0_rd_out[182]
  PIN r0_rd_out[183]
    DIRECTION OUTPUT ;
    USE SIGNAL ;
    SHAPE ABUTMENT ;
    PORT
      LAYER M3 ;
      RECT 52.623 19.873 52.641 19.927 ;
    END
  END r0_rd_out[183]
  PIN r0_rd_out[184]
    DIRECTION OUTPUT ;
    USE SIGNAL ;
    SHAPE ABUTMENT ;
    PORT
      LAYER M3 ;
      RECT 52.911 19.873 52.929 19.927 ;
    END
  END r0_rd_out[184]
  PIN r0_rd_out[185]
    DIRECTION OUTPUT ;
    USE SIGNAL ;
    SHAPE ABUTMENT ;
    PORT
      LAYER M3 ;
      RECT 53.199 19.873 53.217 19.927 ;
    END
  END r0_rd_out[185]
  PIN r0_rd_out[186]
    DIRECTION OUTPUT ;
    USE SIGNAL ;
    SHAPE ABUTMENT ;
    PORT
      LAYER M3 ;
      RECT 53.487 19.873 53.505 19.927 ;
    END
  END r0_rd_out[186]
  PIN r0_rd_out[187]
    DIRECTION OUTPUT ;
    USE SIGNAL ;
    SHAPE ABUTMENT ;
    PORT
      LAYER M3 ;
      RECT 53.775 19.873 53.793 19.927 ;
    END
  END r0_rd_out[187]
  PIN r0_rd_out[188]
    DIRECTION OUTPUT ;
    USE SIGNAL ;
    SHAPE ABUTMENT ;
    PORT
      LAYER M3 ;
      RECT 54.063 19.873 54.081 19.927 ;
    END
  END r0_rd_out[188]
  PIN r0_rd_out[189]
    DIRECTION OUTPUT ;
    USE SIGNAL ;
    SHAPE ABUTMENT ;
    PORT
      LAYER M3 ;
      RECT 54.351 19.873 54.369 19.927 ;
    END
  END r0_rd_out[189]
  PIN r0_rd_out[190]
    DIRECTION OUTPUT ;
    USE SIGNAL ;
    SHAPE ABUTMENT ;
    PORT
      LAYER M3 ;
      RECT 54.639 19.873 54.657 19.927 ;
    END
  END r0_rd_out[190]
  PIN r0_rd_out[191]
    DIRECTION OUTPUT ;
    USE SIGNAL ;
    SHAPE ABUTMENT ;
    PORT
      LAYER M3 ;
      RECT 54.927 19.873 54.945 19.927 ;
    END
  END r0_rd_out[191]
  PIN r0_rd_out[192]
    DIRECTION OUTPUT ;
    USE SIGNAL ;
    SHAPE ABUTMENT ;
    PORT
      LAYER M3 ;
      RECT 55.215 19.873 55.233 19.927 ;
    END
  END r0_rd_out[192]
  PIN w0_addr_in[0]
    DIRECTION INPUT ;
    USE SIGNAL ;
    SHAPE ABUTMENT ;
    PORT
      LAYER M4 ;
      RECT 0.000 14.388 0.072 14.412 ;
    END
  END w0_addr_in[0]
  PIN w0_addr_in[1]
    DIRECTION INPUT ;
    USE SIGNAL ;
    SHAPE ABUTMENT ;
    PORT
      LAYER M4 ;
      RECT 0.000 14.532 0.072 14.556 ;
    END
  END w0_addr_in[1]
  PIN w0_addr_in[2]
    DIRECTION INPUT ;
    USE SIGNAL ;
    SHAPE ABUTMENT ;
    PORT
      LAYER M4 ;
      RECT 61.460 14.100 61.532 14.124 ;
    END
  END w0_addr_in[2]
  PIN w0_addr_in[3]
    DIRECTION INPUT ;
    USE SIGNAL ;
    SHAPE ABUTMENT ;
    PORT
      LAYER M4 ;
      RECT 61.460 14.244 61.532 14.268 ;
    END
  END w0_addr_in[3]
  PIN r0_addr_in[0]
    DIRECTION INPUT ;
    USE SIGNAL ;
    SHAPE ABUTMENT ;
    PORT
      LAYER M4 ;
      RECT 0.000 14.676 0.072 14.700 ;
    END
  END r0_addr_in[0]
  PIN r0_addr_in[1]
    DIRECTION INPUT ;
    USE SIGNAL ;
    SHAPE ABUTMENT ;
    PORT
      LAYER M4 ;
      RECT 0.000 14.820 0.072 14.844 ;
    END
  END r0_addr_in[1]
  PIN r0_addr_in[2]
    DIRECTION INPUT ;
    USE SIGNAL ;
    SHAPE ABUTMENT ;
    PORT
      LAYER M4 ;
      RECT 61.460 14.388 61.532 14.412 ;
    END
  END r0_addr_in[2]
  PIN r0_addr_in[3]
    DIRECTION INPUT ;
    USE SIGNAL ;
    SHAPE ABUTMENT ;
    PORT
      LAYER M4 ;
      RECT 61.460 14.532 61.532 14.556 ;
    END
  END r0_addr_in[3]
  PIN w0_we_in
    DIRECTION INPUT ;
    USE SIGNAL ;
    SHAPE ABUTMENT ;
    PORT
      LAYER M3 ;
      RECT 55.503 19.873 55.521 19.927 ;
    END
  END w0_we_in
  PIN w0_ce_in
    DIRECTION INPUT ;
    USE SIGNAL ;
    SHAPE ABUTMENT ;
    PORT
      LAYER M3 ;
      RECT 55.791 19.873 55.809 19.927 ;
    END
  END w0_ce_in
  PIN w0_clk
    DIRECTION INPUT ;
    USE SIGNAL ;
    SHAPE ABUTMENT ;
    PORT
      LAYER M3 ;
      RECT 56.079 19.873 56.097 19.927 ;
    END
  END w0_clk
  PIN r0_ce_in
    DIRECTION INPUT ;
    USE SIGNAL ;
    SHAPE ABUTMENT ;
    PORT
      LAYER M3 ;
      RECT 56.367 19.873 56.385 19.927 ;
    END
  END r0_ce_in
  PIN r0_clk
    DIRECTION INPUT ;
    USE SIGNAL ;
    SHAPE ABUTMENT ;
    PORT
      LAYER M3 ;
      RECT 56.655 19.873 56.673 19.927 ;
    END
  END r0_clk
  PIN VSS
    DIRECTION INOUT ;
    USE GROUND ;
    PORT
      LAYER M4 ;
      RECT 0.216 0.240 61.316 0.336 ;
      RECT 0.216 1.008 61.316 1.104 ;
      RECT 0.216 1.776 61.316 1.872 ;
      RECT 0.216 2.544 61.316 2.640 ;
      RECT 0.216 3.312 61.316 3.408 ;
      RECT 0.216 4.080 61.316 4.176 ;
      RECT 0.216 4.848 61.316 4.944 ;
      RECT 0.216 5.616 61.316 5.712 ;
      RECT 0.216 6.384 61.316 6.480 ;
      RECT 0.216 7.152 61.316 7.248 ;
      RECT 0.216 7.920 61.316 8.016 ;
      RECT 0.216 8.688 61.316 8.784 ;
      RECT 0.216 9.456 61.316 9.552 ;
      RECT 0.216 10.224 61.316 10.320 ;
      RECT 0.216 10.992 61.316 11.088 ;
      RECT 0.216 11.760 61.316 11.856 ;
      RECT 0.216 12.528 61.316 12.624 ;
      RECT 0.216 13.296 61.316 13.392 ;
      RECT 0.216 14.064 61.316 14.160 ;
      RECT 0.216 14.832 61.316 14.928 ;
      RECT 0.216 15.600 61.316 15.696 ;
      RECT 0.216 16.368 61.316 16.464 ;
      RECT 0.216 17.136 61.316 17.232 ;
      RECT 0.216 17.904 61.316 18.000 ;
      RECT 0.216 18.672 61.316 18.768 ;
      RECT 0.216 19.440 61.316 19.536 ;
    END
  END VSS
  PIN VDD
    DIRECTION INOUT ;
    USE POWER ;
    PORT
      LAYER M4 ;
      RECT 0.216 0.240 61.316 0.336 ;
      RECT 0.216 1.008 61.316 1.104 ;
      RECT 0.216 1.776 61.316 1.872 ;
      RECT 0.216 2.544 61.316 2.640 ;
      RECT 0.216 3.312 61.316 3.408 ;
      RECT 0.216 4.080 61.316 4.176 ;
      RECT 0.216 4.848 61.316 4.944 ;
      RECT 0.216 5.616 61.316 5.712 ;
      RECT 0.216 6.384 61.316 6.480 ;
      RECT 0.216 7.152 61.316 7.248 ;
      RECT 0.216 7.920 61.316 8.016 ;
      RECT 0.216 8.688 61.316 8.784 ;
      RECT 0.216 9.456 61.316 9.552 ;
      RECT 0.216 10.224 61.316 10.320 ;
      RECT 0.216 10.992 61.316 11.088 ;
      RECT 0.216 11.760 61.316 11.856 ;
      RECT 0.216 12.528 61.316 12.624 ;
      RECT 0.216 13.296 61.316 13.392 ;
      RECT 0.216 14.064 61.316 14.160 ;
      RECT 0.216 14.832 61.316 14.928 ;
      RECT 0.216 15.600 61.316 15.696 ;
      RECT 0.216 16.368 61.316 16.464 ;
      RECT 0.216 17.136 61.316 17.232 ;
      RECT 0.216 17.904 61.316 18.000 ;
      RECT 0.216 18.672 61.316 18.768 ;
      RECT 0.216 19.440 61.316 19.536 ;
    END
  END VDD
  OBS
    LAYER M1 ;
    RECT 0 0 61.532 19.927 ;
    LAYER M2 ;
    RECT 0 0 61.532 19.927 ;
    LAYER M3 ;
    RECT 0 0 61.532 19.927 ;
    LAYER M4 ;
    RECT 0 0 61.532 19.927 ;
  END
END fakeram_193x16_1r1w

END LIBRARY
